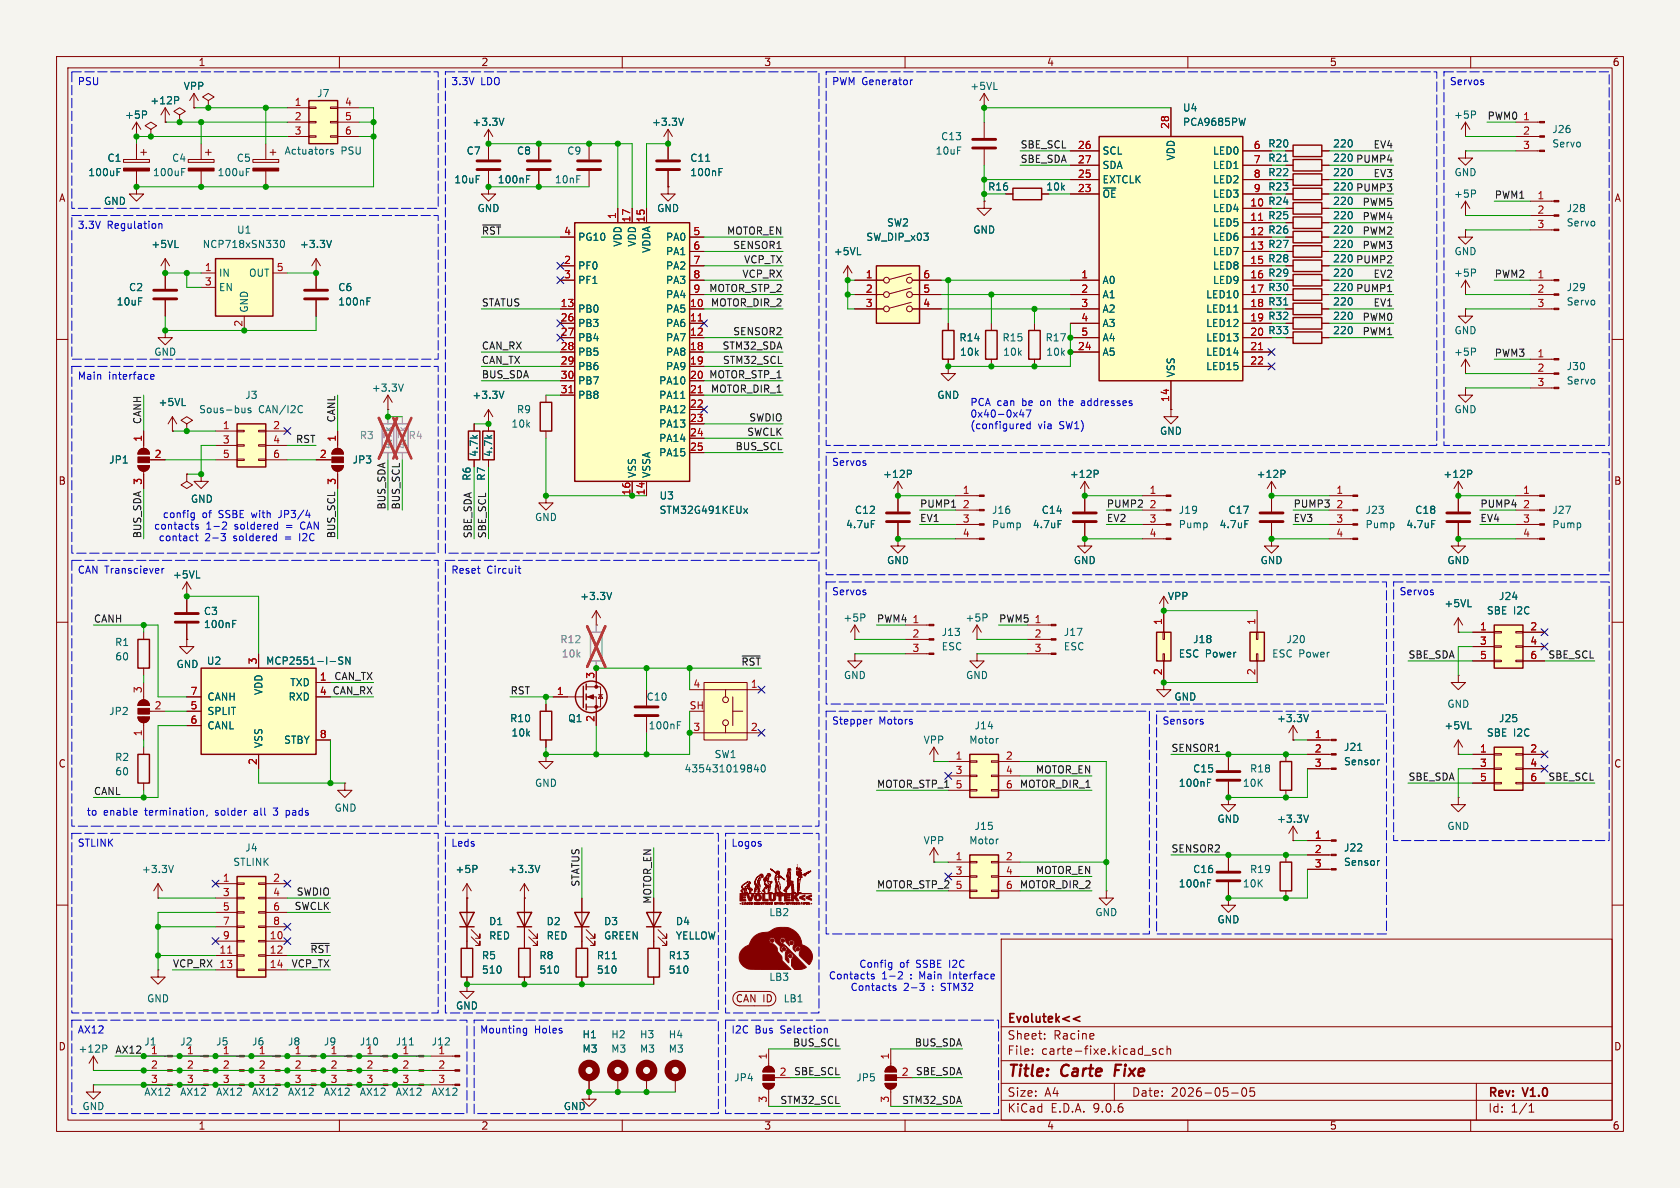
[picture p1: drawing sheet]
<svg xmlns="http://www.w3.org/2000/svg" width="297mm" height="210mm" viewBox="0 0 297 210" stroke-linecap="round" stroke-linejoin="round" font-family="sans-serif">
<defs><g id="words">
<g font-size="2.8" fill="#840000">
<text x="178" y="190.9">Title:</text>
<text x="187.7" y="190.9">Carte</text>
<text x="197.9" y="190.9">Fixe</text>
</g>
<g font-size="2.1" fill="#840000">
<text x="178" y="184">Sheet:</text>
<text x="178" y="181.2">Evolutek&lt;&lt;</text>
<text x="186.2" y="184">Racine</text>
<text x="178" y="186.7">File:</text>
<text x="184.1" y="186.7">carte-fixe.kicad_sch</text>
<text x="178" y="196.9">KiCad</text>
<text x="178" y="194.1">Size:</text>
<text x="184.7" y="194.1">A4</text>
<text x="185.7" y="196.9">E.D.A.</text>
<text x="193.3" y="196.9">9.0.6</text>
<text x="200" y="194.1">Date:</text>
<text x="207" y="194.1">2026-05-05</text>
<text x="263" y="194.3">Rev:</text>
<text x="263" y="196.9">Id:</text>
<text x="267.1" y="196.9">1/1</text>
<text x="269.4" y="194.3">V1.0</text>
</g>
<g font-size="1.8" fill="#840000">
<text x="35" y="11.9">1</text>
<text x="85" y="11.9">2</text>
<text x="135" y="11.9">3</text>
<text x="185" y="11.9">4</text>
<text x="235" y="11.9">5</text>
<text x="285" y="11.9">6</text>
<text x="10.3" y="35.9">A</text>
<text x="285.3" y="35.9">A</text>
<text x="10.3" y="85.9">B</text>
<text x="285.3" y="85.9">B</text>
<text x="10.3" y="135.9">C</text>
<text x="285.3" y="135.9">C</text>
<text x="130" y="177.4">CAN ID</text>
<text x="10.3" y="185.9">D</text>
<text x="285.3" y="185.9">D</text>
<text x="35" y="199.9">1</text>
<text x="85" y="199.9">2</text>
<text x="135" y="199.9">3</text>
<text x="185" y="199.9">4</text>
<text x="235" y="199.9">5</text>
<text x="285" y="199.9">6</text>
</g>
<g font-size="1.8" fill="#0000c2">
<text x="13.7" y="15.4">PSU</text>
<text x="79.7" y="15.4">3.3V</text>
<text x="85" y="15.4">LDO</text>
<text x="147" y="15.4">PWM Generator</text>
<text x="256.2" y="15.4">Servos</text>
<text x="13.7" y="40.8">3.3V</text>
<text x="18.9" y="40.8">Regulation</text>
<text x="13.7" y="67.4">Main</text>
<text x="19.2" y="67.4">interface</text>
<text x="171.4" y="71.9">PCA can</text>
<text x="180.8" y="71.9">be</text>
<text x="184.2" y="71.9">on</text>
<text x="187.7" y="71.9">the</text>
<text x="191.8" y="71.9">addresses</text>
<text x="171.4" y="73.9">0x40-0x47</text>
<text x="171.4" y="76">(configured</text>
<text x="183.5" y="76">via</text>
<text x="187.4" y="76">SW1)</text>
<text x="147" y="82.7">Servos</text>
<text x="27.1" y="93.8">contacts</text>
<text x="28" y="95.9">contact</text>
<text x="28.7" y="91.8">config</text>
<text x="35.7" y="91.8">of</text>
<text x="36.2" y="95.9">2-3</text>
<text x="36.4" y="93.8">1-2</text>
<text x="38.8" y="91.8">SSBE</text>
<text x="41.4" y="95.9">soldered</text>
<text x="41.6" y="93.8">soldered</text>
<text x="44.8" y="91.8">with</text>
<text x="49.8" y="91.8">JP3/4</text>
<text x="50.6" y="95.9">=</text>
<text x="50.9" y="93.8">=</text>
<text x="53.4" y="95.9">I2C</text>
<text x="53.6" y="93.8">CAN</text>
<text x="13.7" y="101.7">CAN Transciever</text>
<text x="79.7" y="101.7">Reset</text>
<text x="86.1" y="101.7">Circuit</text>
<text x="147" y="105.5">Servos</text>
<text x="247.3" y="105.5">Servos</text>
<text x="147" y="128.4">Stepper</text>
<text x="155.4" y="128.4">Motors</text>
<text x="205.4" y="128.4">Sensors</text>
<text x="13.7" y="150">STLINK</text>
<text x="15.2" y="144.3">to</text>
<text x="18.3" y="144.3">enable</text>
<text x="25.7" y="144.3">termination,</text>
<text x="38.3" y="144.3">solder</text>
<text x="45.4" y="144.3">all</text>
<text x="49" y="144.3">3</text>
<text x="51.4" y="144.3">pads</text>
<text x="79.7" y="150">Leds</text>
<text x="129.2" y="150">Logos</text>
<text x="146.4" y="173.3">Contacts</text>
<text x="151.8" y="171.3">Config</text>
<text x="155.9" y="173.3">1-2</text>
<text x="159" y="171.3">of</text>
<text x="161.1" y="173.3">:</text>
<text x="162.1" y="171.3">SSBE</text>
<text x="162.8" y="173.3">Main</text>
<text x="168.1" y="171.3">I2C</text>
<text x="168.4" y="173.3">Interface</text>
<text x="150.3" y="175.4">Contacts</text>
<text x="159.7" y="175.4">2-3</text>
<text x="164.9" y="175.4">:</text>
<text x="166.7" y="175.4">STM32</text>
<text x="13.7" y="183">AX12</text>
<text x="84.8" y="183">Mounting</text>
<text x="94.5" y="183">Holes</text>
<text x="129.2" y="183">I2C</text>
<text x="133.5" y="183">Bus</text>
<text x="138.1" y="183">Selection</text>
</g>
<g font-size="1.8" fill="#006464">
<text x="32.4" y="16.1">VPP</text>
<text x="56" y="17.4">J7</text>
<text x="171.4" y="16.1">+5VL</text>
<text x="22" y="21.2">+5P</text>
<text x="26.5" y="18.6">+12P</text>
<text x="83.4" y="22.5">+3.3V</text>
<text x="115.2" y="22.5">+3.3V</text>
<text x="209" y="19.9">U4</text>
<text x="209" y="22.5">PCA9685PW</text>
<text x="257" y="21.2">+5P</text>
<text x="274.3" y="23.7">J26</text>
<text x="18.9" y="28.8">C1</text>
<text x="30.3" y="28.8">C4</text>
<text x="41.8" y="28.8">C5</text>
<text x="50.2" y="27.5">Actuators</text>
<text x="60.3" y="27.5">PSU</text>
<text x="82.4" y="27.5">C7</text>
<text x="91.3" y="27.5">C8</text>
<text x="100.2" y="27.5">C9</text>
<text x="121.9" y="28.8">C11</text>
<text x="165.3" y="27.5">10uF</text>
<text x="166.3" y="25">C13</text>
<text x="194.8" y="27.5">SCL</text>
<text x="207.9" y="28.5" transform="rotate(-90 207.9 28.5)">VDD</text>
<text x="214.3" y="27.5">LED0</text>
<text x="224.1" y="26.3">R20</text>
<text x="224.1" y="28.8">R21</text>
<text x="235.6" y="26.3">220</text>
<text x="235.6" y="28.8">220</text>
<text x="274.3" y="26.3">Servo</text>
<text x="15.5" y="31.3">100uF</text>
<text x="26.9" y="31.3">100uF</text>
<text x="38.4" y="31.3">100uF</text>
<text x="80.2" y="32.6">10uF</text>
<text x="87.9" y="32.6">100nF</text>
<text x="98" y="32.6">10nF</text>
<text x="121.9" y="31.3">100nF</text>
<text x="174.6" y="33.9">R16</text>
<text x="184.9" y="33.9">10k</text>
<text x="194.8" y="30.1">SDA</text>
<text x="194.8" y="32.6">EXTCLK</text>
<text x="194.8" y="35.2">~{OE}</text>
<text x="214.3" y="30.1">LED1</text>
<text x="214.3" y="32.6">LED2</text>
<text x="214.3" y="35.2">LED3</text>
<text x="224.1" y="31.3">R22</text>
<text x="224.1" y="33.9">R23</text>
<text x="235.6" y="31.3">220</text>
<text x="235.6" y="33.9">220</text>
<text x="257" y="35.2">+5P</text>
<text x="257" y="31.3">GND</text>
<text x="18.3" y="36.4">GND</text>
<text x="41.8" y="41.5">U1</text>
<text x="84.3" y="37.7">GND</text>
<text x="116.1" y="37.7">GND</text>
<text x="156.7" y="40.2">SW2</text>
<text x="172" y="41.5">GND</text>
<text x="214.3" y="37.7">LED4</text>
<text x="214.3" y="40.2">LED5</text>
<text x="220.9" y="36.6">10 R24</text>
<text x="220.9" y="39.1">11 R25</text>
<text x="220.9" y="41.7">12 R26</text>
<text x="235.6" y="41.5">220</text>
<text x="235.6" y="39">220</text>
<text x="235.6" y="36.4">220</text>
<text x="276.9" y="40.2">Servo</text>
<text x="276.9" y="37.7">J28</text>
<text x="26.7" y="44">+5VL</text>
<text x="35.7" y="44">NCP718xSN330</text>
<text x="52.9" y="44">+3.3V</text>
<text x="102.1" y="42.8">PG10</text>
<text x="102.1" y="47.9">PF0</text>
<text x="110.1" y="43.7" transform="rotate(-90 110.1 43.7)">VDD</text>
<text x="112.6" y="43.7" transform="rotate(-90 112.6 43.7)">VDD</text>
<text x="115.2" y="44.8" transform="rotate(-90 115.2 44.8)">VDDA</text>
<text x="117.6" y="42.8">PA0</text>
<text x="117.6" y="45.3">PA1</text>
<text x="117.6" y="47.9">PA2</text>
<text x="147.3" y="45.3">+5VL</text>
<text x="153.1" y="42.8">SW_DIP_x03</text>
<text x="214.3" y="42.8">LED6</text>
<text x="214.3" y="45.3">LED7</text>
<text x="214.3" y="47.9">LED8</text>
<text x="220.9" y="44.2">13 R27</text>
<text x="220.9" y="46.7">15 R28</text>
<text x="235.6" y="44">220</text>
<text x="235.6" y="46.6">220</text>
<text x="257" y="45.3">GND</text>
<text x="22.7" y="51.7">C2</text>
<text x="38.6" y="49.1">IN</text>
<text x="38.6" y="51.7">EN</text>
<text x="43.9" y="49.1">OUT</text>
<text x="59.7" y="51.7">C6</text>
<text x="102.1" y="50.4">PF1</text>
<text x="117.6" y="50.4">PA3</text>
<text x="117.6" y="52.9">PA4</text>
<text x="194.8" y="50.4">A0</text>
<text x="194.8" y="52.9">A1</text>
<text x="213.1" y="52.9">LED10</text>
<text x="214.3" y="50.4">LED9</text>
<text x="220.9" y="49.3">16 R29</text>
<text x="220.9" y="51.8">17 R30</text>
<text x="235.6" y="49.1">220</text>
<text x="235.6" y="51.7">220</text>
<text x="257" y="49.1">+5P</text>
<text x="276.9" y="51.7">J29</text>
<text x="20.5" y="54.2">10uF</text>
<text x="44" y="55.4" transform="rotate(-90 44 55.4)">GND</text>
<text x="59.7" y="54.2">100nF</text>
<text x="102.1" y="55.5">PB0</text>
<text x="102.1" y="58">PB3</text>
<text x="117.6" y="55.5">PA5</text>
<text x="117.6" y="58">PA6</text>
<text x="194.8" y="55.5">A2</text>
<text x="194.8" y="58">A3</text>
<text x="213.1" y="55.5">LED11</text>
<text x="213.1" y="58">LED12</text>
<text x="220.9" y="54.4">18 R31</text>
<text x="220.9" y="56.9">19 R32</text>
<text x="220.9" y="59.4">20 R33</text>
<text x="235.6" y="54.2">220</text>
<text x="235.6" y="56.7">220</text>
<text x="235.6" y="59.3">220</text>
<text x="257" y="59.3">GND</text>
<text x="276.9" y="54.2">Servo</text>
<text x="27.2" y="63.1">GND</text>
<text x="102.1" y="60.6">PB4</text>
<text x="102.1" y="63.1">PB5</text>
<text x="102.1" y="65.6">PB6</text>
<text x="117.6" y="60.6">PA7</text>
<text x="117.6" y="63.1">PA8</text>
<text x="117.6" y="65.6">PA9</text>
<text x="169.5" y="60.6">R14</text>
<text x="169.6" y="63.1">10k</text>
<text x="177.1" y="60.6">R15</text>
<text x="177.2" y="63.1">10k</text>
<text x="184.7" y="60.6">R17</text>
<text x="184.9" y="63.1">10k</text>
<text x="194.8" y="60.6">A4</text>
<text x="194.8" y="63.1">A5</text>
<text x="213.1" y="60.6">LED13</text>
<text x="213.1" y="63.1">LED14</text>
<text x="213.1" y="65.6">LED15</text>
<text x="257" y="63.1">+5P</text>
<text x="276.9" y="65.6">J30</text>
<text x="27.9" y="72">+5VL</text>
<text x="43.3" y="70.7">J3</text>
<text x="65.6" y="69.4">+3.3V</text>
<text x="83.4" y="70.7">+3.3V</text>
<text x="102.1" y="68.2">PB7</text>
<text x="102.1" y="70.7">PB8</text>
<text x="116.4" y="68.2">PA10</text>
<text x="116.4" y="70.7">PA11</text>
<text x="165.6" y="70.7">GND</text>
<text x="207.9" y="66.8" transform="rotate(-90 207.9 66.8)">VSS</text>
<text x="276.9" y="68.2">Servo</text>
<text x="35.1" y="73.3">Sous-bus</text>
<text x="45.7" y="73.3">CAN/I2C</text>
<text x="90.3" y="75.8">10k</text>
<text x="91.3" y="73.3">R9</text>
<text x="116.4" y="73.3">PA12</text>
<text x="116.4" y="75.8">PA13</text>
<text x="205" y="77.1">GND</text>
<text x="257" y="73.3">GND</text>
<text x="19.2" y="82.1">JP1</text>
<text x="62.2" y="82.1">JP3</text>
<text x="84.7" y="80.9" transform="rotate(-90 84.7 80.9)">4.7k</text>
<text x="87.2" y="80.9" transform="rotate(-90 87.2 80.9)">4.7k</text>
<text x="116.4" y="78.3">PA14</text>
<text x="116.4" y="80.9">PA15</text>
<text x="33.7" y="89.1">GND</text>
<text x="83.4" y="85.1" transform="rotate(-90 83.4 85.1)">R6</text>
<text x="86" y="85.1" transform="rotate(-90 86 85.1)">R7</text>
<text x="112.6" y="84.6" transform="rotate(-90 112.6 84.6)">VSS</text>
<text x="115.2" y="84.6" transform="rotate(-90 115.2 84.6)">VSSA</text>
<text x="116.5" y="88.5">U3</text>
<text x="156" y="84.7">+12P</text>
<text x="189" y="84.7">+12P</text>
<text x="222.1" y="84.7">+12P</text>
<text x="255.1" y="84.7">+12P</text>
<text x="94.5" y="92.3">GND</text>
<text x="116.5" y="91">STM32G491KEUx</text>
<text x="149.5" y="93.6">4.7uF</text>
<text x="151" y="91">C12</text>
<text x="175.3" y="93.6">Pump</text>
<text x="175.3" y="91">J16</text>
<text x="182.5" y="93.6">4.7uF</text>
<text x="184.1" y="91">C14</text>
<text x="208.3" y="93.6">Pump</text>
<text x="208.3" y="91">J19</text>
<text x="215.5" y="93.6">4.7uF</text>
<text x="217.1" y="91">C17</text>
<text x="241.3" y="93.6">Pump</text>
<text x="241.3" y="91">J23</text>
<text x="248.5" y="93.6">4.7uF</text>
<text x="250.1" y="91">C18</text>
<text x="274.3" y="93.6">Pump</text>
<text x="274.3" y="91">J27</text>
<text x="156.7" y="99.9">GND</text>
<text x="189.7" y="99.9">GND</text>
<text x="222.8" y="99.9">GND</text>
<text x="255.8" y="99.9">GND</text>
<text x="30.5" y="102.5">+5VL</text>
<text x="102.5" y="106.3">+3.3V</text>
<text x="206.4" y="106.3">VPP</text>
<text x="255.3" y="107.5">+5VL</text>
<text x="264.9" y="106.3">J24</text>
<text x="36" y="108.9">C3</text>
<text x="36" y="111.2">100nF</text>
<text x="149" y="110.1">+5P</text>
<text x="166.4" y="112.6">J13</text>
<text x="170.6" y="110.1">+5P</text>
<text x="188" y="112.6">J17</text>
<text x="210.8" y="113.9">J18</text>
<text x="227.3" y="113.9">J20</text>
<text x="262.8" y="108.8">SBE</text>
<text x="267.6" y="108.8">I2C</text>
<text x="20.2" y="114.4">R1</text>
<text x="20.3" y="116.9">60</text>
<text x="31.1" y="118.3">GND</text>
<text x="36.5" y="117.7">U2</text>
<text x="46.9" y="117.7">MCP2551-I-SN</text>
<text x="166.4" y="115.2">ESC</text>
<text x="188" y="115.2">ESC</text>
<text x="208.3" y="116.4">ESC Power</text>
<text x="224.8" y="116.4">ESC Power</text>
<text x="36.6" y="124.1">CANH</text>
<text x="46.6" y="123" transform="rotate(-90 46.6 123)">VDD</text>
<text x="50.9" y="124.1">RXD</text>
<text x="51.2" y="121.5">TXD</text>
<text x="114.2" y="124.1">C10</text>
<text x="149.1" y="120.2">GND</text>
<text x="170.7" y="120.2">GND</text>
<text x="207.5" y="124.1">GND</text>
<text x="255.8" y="125.3">GND</text>
<text x="19.2" y="126.6">JP2</text>
<text x="36.6" y="126.6">SPLIT</text>
<text x="36.6" y="129.1">CANL</text>
<text x="50.1" y="131.7">STBY</text>
<text x="90.1" y="127.9">R10</text>
<text x="90.3" y="130.4">10k</text>
<text x="100.3" y="127.9">Q1</text>
<text x="114.6" y="129.1">100nF</text>
<text x="163.2" y="131.7">VPP</text>
<text x="171.3" y="131.7">Motor</text>
<text x="172.2" y="129.1">J14</text>
<text x="225.7" y="127.9">+3.3V</text>
<text x="255.3" y="129.1">+5VL</text>
<text x="262.8" y="130.4">SBE</text>
<text x="264.9" y="127.9">J25</text>
<text x="267.6" y="130.4">I2C</text>
<text x="20.2" y="134.7">R2</text>
<text x="20.3" y="137.3">60</text>
<text x="46.6" y="132.3" transform="rotate(-90 46.6 132.3)">VSS</text>
<text x="120.9" y="136.8">435431019840</text>
<text x="126.2" y="134.2">SW1</text>
<text x="210.8" y="136.8">C15</text>
<text x="220.9" y="136.8">R18</text>
<text x="237.5" y="132.9">J21</text>
<text x="237.5" y="135.5">Sensor</text>
<text x="59.1" y="143.7">GND</text>
<text x="94.5" y="139.3">GND</text>
<text x="208.3" y="139.3">100nF</text>
<text x="219.6" y="139.3">10K</text>
<text x="163.2" y="149.5">VPP</text>
<text x="171.3" y="149.5">Motor</text>
<text x="172.2" y="146.9">J15</text>
<text x="215.1" y="145.6">GND</text>
<text x="225.7" y="145.6">+3.3V</text>
<text x="255.8" y="146.9">GND</text>
<text x="25" y="154.5">+3.3V</text>
<text x="41.1" y="153.3">STLINK</text>
<text x="43.3" y="150.7">J4</text>
<text x="80.4" y="154.5">+5P</text>
<text x="89.8" y="154.5">+3.3V</text>
<text x="210.8" y="154.5">C16</text>
<text x="220.9" y="154.5">R19</text>
<text x="237.5" y="150.7">J22</text>
<text x="237.5" y="153.3">Sensor</text>
<text x="208.3" y="157.1">100nF</text>
<text x="219.6" y="157.1">10K</text>
<text x="86.4" y="163.7">D1</text>
<text x="86.4" y="166.3">RED</text>
<text x="96.5" y="163.7">D2</text>
<text x="96.5" y="166.3">RED</text>
<text x="106.7" y="163.7">D3</text>
<text x="106.7" y="166.3">GREEN</text>
<text x="119.4" y="163.7">D4</text>
<text x="119.4" y="166.3">YELLOW</text>
<text x="135.9" y="162.2">LB2</text>
<text x="193.5" y="162.2">GND</text>
<text x="215.1" y="163.4">GND</text>
<text x="85.1" y="169.8">R5</text>
<text x="85.1" y="172.3">510</text>
<text x="95.3" y="169.8">R8</text>
<text x="95.3" y="172.3">510</text>
<text x="105.4" y="172.3">510</text>
<text x="105.4" y="169.8">R11</text>
<text x="118.1" y="172.3">510</text>
<text x="118.1" y="169.8">R13</text>
<text x="135.9" y="173.6">LB3</text>
<text x="25.9" y="177.4">GND</text>
<text x="80.5" y="178.7">GND</text>
<text x="138.4" y="177.4">LB1</text>
<text x="31.8" y="185">J2</text>
<text x="38.1" y="185">J5</text>
<text x="44.5" y="185">J6</text>
<text x="50.8" y="185">J8</text>
<text x="57.2" y="185">J9</text>
<text x="63.5" y="185">J10</text>
<text x="69.9" y="185">J11</text>
<text x="76.2" y="185">J12</text>
<text x="102.9" y="183.7">H1</text>
<text x="108" y="183.7">H2</text>
<text x="113" y="183.7">H3</text>
<text x="118.1" y="183.7">H4</text>
<text x="13.8" y="186.3">+12P</text>
<text x="26.6" y="186.4">1</text>
<text x="32.9" y="186.4">1</text>
<text x="39.3" y="186.4">1</text>
<text x="45.6" y="186.4">1</text>
<text x="52" y="186.4">1</text>
<text x="58.3" y="186.4">1</text>
<text x="64.7" y="186.4">1</text>
<text x="71" y="186.4">1</text>
<text x="77.4" y="186.4">1</text>
<text x="102.9" y="186.3">M3</text>
<text x="108" y="186.3">M3</text>
<text x="113" y="186.3">M3</text>
<text x="118.1" y="186.3">M3</text>
<text x="129.7" y="191.4">JP4</text>
<text x="151.3" y="191.4">JP5</text>
<text x="14.5" y="196.4">GND</text>
<text x="25.4" y="193.9">AX12</text>
<text x="31.8" y="193.9">AX12</text>
<text x="38.1" y="193.9">AX12</text>
<text x="44.5" y="193.9">AX12</text>
<text x="50.8" y="193.9">AX12</text>
<text x="57.2" y="193.9">AX12</text>
<text x="63.5" y="193.9">AX12</text>
<text x="69.9" y="193.9">AX12</text>
<text x="76.2" y="193.9">AX12</text>
<text x="99.6" y="196.4">GND</text>
</g>
<g font-size="1.8" fill="#a90000">
<text x="52" y="18.8">1</text>
<text x="52" y="21.3">2</text>
<text x="52" y="23.9">3</text>
<text x="60.9" y="18.8">4</text>
<text x="60.9" y="21.3">5</text>
<text x="60.9" y="23.9">6</text>
<text x="206.8" y="22.9" transform="rotate(-90 206.8 22.9)">28</text>
<text x="269.2" y="21.3">1</text>
<text x="269.2" y="23.9">2</text>
<text x="190.5" y="26.4">26</text>
<text x="190.5" y="29">27</text>
<text x="221.5" y="26.4">6</text>
<text x="221.5" y="29">7</text>
<text x="269.2" y="26.4">3</text>
<text x="190.5" y="31.5">25</text>
<text x="190.5" y="34">23</text>
<text x="221.5" y="31.5">8</text>
<text x="221.5" y="34">9</text>
<text x="271.7" y="35.3">1</text>
<text x="99.6" y="41.7">4</text>
<text x="109" y="38.8" transform="rotate(-90 109 38.8)">1</text>
<text x="111.5" y="39.4" transform="rotate(-90 111.5 39.4)">17</text>
<text x="114" y="39.4" transform="rotate(-90 114 39.4)">15</text>
<text x="122.5" y="41.7">5</text>
<text x="271.7" y="37.8">2</text>
<text x="271.7" y="40.4">3</text>
<text x="99.6" y="46.7">2</text>
<text x="122.5" y="44.2">6</text>
<text x="122.5" y="46.7">7</text>
<text x="36.1" y="48">1</text>
<text x="36.1" y="50.5">3</text>
<text x="48.8" y="48">5</text>
<text x="99.6" y="49.3">3</text>
<text x="122.5" y="49.3">8</text>
<text x="122.5" y="51.8">9</text>
<text x="153" y="49.3">1</text>
<text x="153" y="51.8">2</text>
<text x="163.1" y="49.3">6</text>
<text x="163.1" y="51.8">5</text>
<text x="191.1" y="49.3">1</text>
<text x="191.1" y="51.8">2</text>
<text x="271.7" y="49.3">1</text>
<text x="271.7" y="51.8">2</text>
<text x="42.9" y="57.9" transform="rotate(-90 42.9 57.9)">2</text>
<text x="99" y="54.4">13</text>
<text x="99" y="56.9">26</text>
<text x="99" y="59.4">27</text>
<text x="121.9" y="54.4">10</text>
<text x="121.9" y="56.9">11</text>
<text x="121.9" y="59.4">12</text>
<text x="153" y="54.4">3</text>
<text x="163.1" y="54.4">4</text>
<text x="191.1" y="54.4">3</text>
<text x="191.1" y="56.9">4</text>
<text x="191.1" y="59.4">5</text>
<text x="271.7" y="54.4">3</text>
<text x="99" y="62">28</text>
<text x="99" y="64.5">29</text>
<text x="121.9" y="62">18</text>
<text x="121.9" y="64.5">19</text>
<text x="190.5" y="62">24</text>
<text x="220.9" y="62">21</text>
<text x="220.9" y="64.5">22</text>
<text x="271.7" y="63.2">1</text>
<text x="271.7" y="65.8">2</text>
<text x="99" y="67.1">30</text>
<text x="99" y="69.6">31</text>
<text x="121.9" y="67.1">20</text>
<text x="121.9" y="69.6">21</text>
<text x="206.8" y="71.2" transform="rotate(-90 206.8 71.2)">14</text>
<text x="271.7" y="68.3">3</text>
<text x="39.3" y="75.9">1</text>
<text x="48.2" y="75.9">2</text>
<text x="121.9" y="72.1">22</text>
<text x="121.9" y="74.7">23</text>
<text x="121.9" y="77.2">24</text>
<text x="25.1" y="78.2" transform="rotate(-90 25.1 78.2)">1</text>
<text x="27.2" y="81">2</text>
<text x="39.3" y="78.5">3</text>
<text x="39.3" y="81">5</text>
<text x="48.2" y="78.5">4</text>
<text x="48.2" y="81">6</text>
<text x="56.4" y="81">2</text>
<text x="59.4" y="78.2" transform="rotate(-90 59.4 78.2)">1</text>
<text x="121.9" y="79.8">25</text>
<text x="25.1" y="85.8" transform="rotate(-90 25.1 85.8)">3</text>
<text x="59.4" y="85.8" transform="rotate(-90 59.4 85.8)">3</text>
<text x="111.5" y="87.7" transform="rotate(-90 111.5 87.7)">16</text>
<text x="114" y="87.7" transform="rotate(-90 114 87.7)">14</text>
<text x="170.1" y="87.4">1</text>
<text x="170.1" y="89.9">2</text>
<text x="203.1" y="87.4">1</text>
<text x="203.1" y="89.9">2</text>
<text x="236.1" y="87.4">1</text>
<text x="236.1" y="89.9">2</text>
<text x="269.2" y="87.4">1</text>
<text x="269.2" y="89.9">2</text>
<text x="170.1" y="92.5">3</text>
<text x="170.1" y="95">4</text>
<text x="203.1" y="92.5">3</text>
<text x="203.1" y="95">4</text>
<text x="236.1" y="92.5">3</text>
<text x="236.1" y="95">4</text>
<text x="269.2" y="92.5">3</text>
<text x="269.2" y="95">4</text>
<text x="161.2" y="110.2">1</text>
<text x="161.2" y="112.8">2</text>
<text x="182.8" y="110.2">1</text>
<text x="182.8" y="112.8">2</text>
<text x="205.5" y="110.6" transform="rotate(-90 205.5 110.6)">1</text>
<text x="222" y="110.6" transform="rotate(-90 222 110.6)">1</text>
<text x="261.5" y="111.5">1</text>
<text x="270.4" y="111.5">2</text>
<text x="45.5" y="117.5" transform="rotate(-90 45.5 117.5)">3</text>
<text x="161.2" y="115.3">3</text>
<text x="182.8" y="115.3">3</text>
<text x="205.5" y="119.5" transform="rotate(-90 205.5 119.5)">2</text>
<text x="222" y="119.5" transform="rotate(-90 222 119.5)">2</text>
<text x="261.5" y="114">3</text>
<text x="261.5" y="116.6">5</text>
<text x="270.4" y="114">4</text>
<text x="270.4" y="116.6">6</text>
<text x="25.1" y="122.6" transform="rotate(-90 25.1 122.6)">3</text>
<text x="27.2" y="125.5">2</text>
<text x="33.6" y="122.9">7</text>
<text x="33.6" y="125.5">5</text>
<text x="56.4" y="120.4">1</text>
<text x="56.4" y="122.9">4</text>
<text x="98.4" y="122.9">1</text>
<text x="105.2" y="120.1" transform="rotate(-90 105.2 120.1)">3</text>
<text x="121.8" y="125.5">SH</text>
<text x="122.5" y="121.7">4</text>
<text x="132.6" y="121.7">1</text>
<text x="25.1" y="130.2" transform="rotate(-90 25.1 130.2)">1</text>
<text x="33.6" y="128">6</text>
<text x="56.4" y="130.6">8</text>
<text x="105.2" y="127.7" transform="rotate(-90 105.2 127.7)">2</text>
<text x="122.5" y="129.3">3</text>
<text x="132.6" y="129.3">2</text>
<text x="232.3" y="130.6">1</text>
<text x="45.5" y="135.3" transform="rotate(-90 45.5 135.3)">2</text>
<text x="168.8" y="134.4">1</text>
<text x="168.8" y="136.9">3</text>
<text x="177.7" y="134.4">2</text>
<text x="177.7" y="136.9">4</text>
<text x="232.3" y="133.1">2</text>
<text x="232.3" y="135.6">3</text>
<text x="261.5" y="133.1">1</text>
<text x="261.5" y="135.6">3</text>
<text x="270.4" y="133.1">2</text>
<text x="270.4" y="135.6">4</text>
<text x="168.8" y="139.4">5</text>
<text x="177.7" y="139.4">6</text>
<text x="261.5" y="138.2">5</text>
<text x="270.4" y="138.2">6</text>
<text x="232.3" y="148.3">1</text>
<text x="39.3" y="156">1</text>
<text x="48.2" y="156">2</text>
<text x="168.8" y="152.1">1</text>
<text x="168.8" y="154.7">3</text>
<text x="177.7" y="152.1">2</text>
<text x="177.7" y="154.7">4</text>
<text x="232.3" y="150.9">2</text>
<text x="232.3" y="153.4">3</text>
<text x="39.3" y="158.5">3</text>
<text x="39.3" y="161">5</text>
<text x="48.2" y="158.5">4</text>
<text x="48.2" y="161">6</text>
<text x="168.8" y="157.2">5</text>
<text x="177.7" y="157.2">6</text>
<text x="39.3" y="163.6">7</text>
<text x="39.3" y="166.1">9</text>
<text x="47.6" y="166.1">10</text>
<text x="48.2" y="163.6">8</text>
<text x="38.7" y="168.7">11</text>
<text x="47.6" y="168.7">12</text>
<text x="47.6" y="171.2">14</text>
<text x="26.6" y="189">2</text>
<text x="26.6" y="191.5">3</text>
<text x="32.9" y="189">2</text>
<text x="32.9" y="191.5">3</text>
<text x="39.3" y="189">2</text>
<text x="39.3" y="191.5">3</text>
<text x="45.6" y="189">2</text>
<text x="45.6" y="191.5">3</text>
<text x="52" y="189">2</text>
<text x="52" y="191.5">3</text>
<text x="58.3" y="189">2</text>
<text x="58.3" y="191.5">3</text>
<text x="64.7" y="189">2</text>
<text x="64.7" y="191.5">3</text>
<text x="71" y="189">2</text>
<text x="71" y="191.5">3</text>
<text x="77.4" y="189">2</text>
<text x="77.4" y="191.5">3</text>
<text x="135.6" y="187.4" transform="rotate(-90 135.6 187.4)">1</text>
<text x="137.7" y="190.2">2</text>
<text x="157.2" y="187.4" transform="rotate(-90 157.2 187.4)">1</text>
<text x="159.3" y="190.2">2</text>
<text x="135.6" y="195" transform="rotate(-90 135.6 195)">3</text>
<text x="157.2" y="195" transform="rotate(-90 157.2 195)">3</text>
</g>
<g font-size="1.8" fill="#0f0f0f">
<text x="262.9" y="21.2">PWM0</text>
<text x="180.3" y="26.3">SBE_SCL</text>
<text x="180.3" y="28.9">SBE_SDA</text>
<text x="235.6" y="28.8">220 PUMP4</text>
<text x="242.7" y="26.3">EV4</text>
<text x="235.6" y="33.9">220 PUMP3</text>
<text x="242.7" y="31.4">EV3</text>
<text x="264.2" y="35.2">PWM1</text>
<text x="85.1" y="41.6">~{RST}</text>
<text x="128.4" y="41.6">MOTOR_EN</text>
<text x="240.8" y="41.6">PWM2</text>
<text x="240.8" y="39">PWM4</text>
<text x="240.8" y="36.5">PWM5</text>
<text x="129.5" y="44.1">SENSOR1</text>
<text x="131.5" y="46.6">VCP_TX</text>
<text x="235.6" y="46.6">220 PUMP2</text>
<text x="240.8" y="44.1">PWM3</text>
<text x="125.3" y="51.7">MOTOR_STP_2</text>
<text x="131.2" y="49.2">VCP_RX</text>
<text x="235.6" y="51.7">220 PUMP1</text>
<text x="242.7" y="49.2">EV2</text>
<text x="264.2" y="49.2">PWM2</text>
<text x="85.1" y="54.3">STATUS</text>
<text x="125.6" y="54.3">MOTOR_DIR_2</text>
<text x="129.5" y="59.3">SENSOR2</text>
<text x="240.8" y="59.3">PWM1</text>
<text x="240.8" y="56.8">PWM0</text>
<text x="242.7" y="54.3">EV1</text>
<text x="85.1" y="64.4">CAN_TX</text>
<text x="85.1" y="61.9">CAN_RX</text>
<text x="127.6" y="61.9">STM32_SDA</text>
<text x="127.7" y="64.4">STM32_SCL</text>
<text x="264.2" y="63.2">PWM3</text>
<text x="85.1" y="67">BUS_SDA</text>
<text x="125.3" y="67">MOTOR_STP_1</text>
<text x="125.6" y="69.5">MOTOR_DIR_1</text>
<text x="25.1" y="75.1" transform="rotate(-90 25.1 75.1)">CANH</text>
<text x="59.3" y="74.8" transform="rotate(-90 59.3 74.8)">CANL</text>
<text x="132" y="77.1">SWCLK</text>
<text x="132.4" y="74.6">SWDIO</text>
<text x="52.2" y="78.4">RST</text>
<text x="129.9" y="79.7">BUS_SCL</text>
<text x="162.6" y="89.8">PUMP1</text>
<text x="195.6" y="89.8">PUMP2</text>
<text x="228.6" y="89.8">PUMP3</text>
<text x="261.6" y="89.8">PUMP4</text>
<text x="25.1" y="95.3" transform="rotate(-90 25.1 95.3)">BUS_SDA 3</text>
<text x="59.3" y="95.3" transform="rotate(-90 59.3 95.3)">BUS_SCL</text>
<text x="68.2" y="90.2" transform="rotate(-90 68.2 90.2)">BUS_SDA</text>
<text x="70.8" y="90.2" transform="rotate(-90 70.8 90.2)">BUS_SCL</text>
<text x="83.5" y="95.3" transform="rotate(-90 83.5 95.3)">SBE_SDA</text>
<text x="86" y="95.3" transform="rotate(-90 86 95.3)">SBE_SCL</text>
<text x="162.6" y="92.4">EV1</text>
<text x="195.6" y="92.4">EV2</text>
<text x="228.6" y="92.4">EV3</text>
<text x="261.6" y="92.4">EV4</text>
<text x="16.5" y="110.1">CANH</text>
<text x="154.9" y="110.1">PWM4</text>
<text x="176.5" y="110.1">PWM5</text>
<text x="131" y="117.8">~{RST}</text>
<text x="248.9" y="116.5">SBE_SDA</text>
<text x="273.6" y="116.5">SBE_SCL</text>
<text x="58.7" y="122.8">CAN_RX</text>
<text x="59" y="120.3">CAN_TX</text>
<text x="90.2" y="122.8">RST</text>
<text x="183" y="136.8">MOTOR_EN</text>
<text x="207" y="133">SENSOR1</text>
<text x="16.5" y="140.6">CANL</text>
<text x="154.9" y="139.4">MOTOR_STP_1</text>
<text x="180.2" y="139.4">MOTOR_DIR_1</text>
<text x="248.9" y="138.1">SBE_SDA</text>
<text x="273.6" y="138.1">SBE_SCL</text>
<text x="183" y="154.6">MOTOR_EN</text>
<text x="207" y="150.8">SENSOR2</text>
<text x="52" y="160.9">SWCLK</text>
<text x="52.4" y="158.4">SWDIO</text>
<text x="102.5" y="156.8" transform="rotate(-90 102.5 156.8)">STATUS</text>
<text x="115.2" y="159.9" transform="rotate(-90 115.2 159.9)">MOTOR_EN</text>
<text x="154.9" y="157.1">MOTOR_STP_2</text>
<text x="180.2" y="157.1">MOTOR_DIR_2</text>
<text x="30.5" y="171.1">VCP_RX 13</text>
<text x="51.4" y="171.1">VCP_TX</text>
<text x="54.8" y="168.6">~{RST}</text>
<text x="25.4" y="185">J1</text>
<text x="140.1" y="185.1">BUS_SCL</text>
<text x="161.6" y="185.1">BUS_SDA</text>
<text x="20.3" y="186.3">AX12</text>
<text x="140.3" y="190.2">SBE_SCL</text>
<text x="161.8" y="190.2">SBE_SDA</text>
<text x="137.9" y="195.2">STM32_SCL</text>
<text x="159.4" y="195.2">STM32_SDA</text>
</g>
<g font-size="1.8" fill="#939391">
<text x="63.5" y="77.8">R3</text>
<text x="72.1" y="77.8">R4</text>
<text x="69.4" y="79.5" transform="rotate(-90 69.4 79.5)">4.7k</text>
<text x="72" y="79.5" transform="rotate(-90 72 79.5)">4.7k</text>
<text x="99" y="113.9">R12</text>
<text x="99.2" y="116.4">10k</text>
</g>
</g></defs>
<path d="M0 0h297v210h-297z" fill="#f5f4ef" stroke="#f5f4ef" stroke-width=".18"/>
<g fill="none" stroke="#840000" stroke-width=".18">
<path d="M10 10h277v190h-277zM12 12h273v186h-273zM60 10v2M110 10v2M160 10v2M210 10v2M260 10v2M177.8 34.3h1.3M184.1 34.3h1.3M10 60h2M285 60h2M10 110h2"/>
<path d="M285 110h2M10 160h2M177 166h108v32h-108zM285 160h2M60 198v2M110 198v2M160 198v2M177 194.5h108M177 191.5h108M177 187.5h108M177 181.5h108M182.5 186.3v.1"/>
<path d="M182.5 185.5v.1M184.7 183.6v.1M184.7 182.8v.1M193.3 182.8l.1 .3-.7 .1M197 191.5v3M202.3 186.5h1.2M204.3 185.5l-.3-.1-.3 .2 .1 .2 .5 .2v.3h-.6M205.7 185.5l-.5-.1-.2 .3v.4l.1 .2h.6M206.3 185.5l.2-.1 .4 .1 .1 .9M206.3 184.9v1.5M210 198v2M217.7 193.2h1.2"/>
<path d="M219.7 192.4l.2-.1a.81 .81 0 0 1 .6 .6 .81 .81 0 0 1-.3 .8l-.2 .1a.81 .81 0 0 1-.3-1.4zM221.7 192.3h-.7v.7l.2-.1h.5l.1 .3-.1 .5-.2 .1-.5-.1M260 198v2M261 191.5v6.5M270.3 196.6h.9M270.3 195.5l.4-.4v1.5"/>
</g>
<path d="M197.3 188.2l-.3 2" fill="none" stroke="#840000" stroke-width=".4"/>
<path d="M190.9 179.7l-1.1 .4 1.1 .4" fill="none" stroke="#840000" stroke-width=".3"/>
<path d="M179.1 33.3h5v2h-5z" fill="none" stroke="#840000" stroke-width=".25"/>
<path d="M154.9 47h7.7v10.2h-7.7z" fill="#ffffc2"/>
<g fill="none" stroke="#840000" stroke-width=".18">
<path d="M86.4 25.4h.1M86.4 33v1.3h1.2l-1.2 1.3-1.3-1.3h1.3M86.4 33h.1M86.4 22.9l-.8 1.2M86.4 22.9l.7 1.2M86.4 22.9v5.3M86.4 30.2v2.8M151.1 49.5h5.1M151.1 52.1h5.1M151.1 54.6h5.1M161.1 48.4l-3.9 1M161.1 50.9l-3.9 1"/>
<path d="M161.1 53.4l-3.9 1.1M161.3 49.5h5.1M161.3 52.1h5.1M161.3 54.6h5.1M68.6 72.4h.1M68.6 69.9l-.8 1.2M68.6 69.9l.7 1.2M68.6 69.9v2.5"/>
<circle cx="156.7" cy="49.5" r=".51"/>
<circle cx="156.7" cy="52.1" r=".51"/>
<circle cx="156.7" cy="54.6" r=".51"/>
<circle cx="160.8" cy="49.5" r=".51"/>
<circle cx="160.8" cy="52.1" r=".51"/>
<circle cx="160.8" cy="54.6" r=".51"/>
</g>
<path d="M154.9 47h7.7v10.2h-7.7z" fill="none" stroke="#840000" stroke-width=".25"/>
<path d="M89.1 20.9l-.4 1.3M71.3 67.9l-.4 1.3" fill="none" stroke="#006464" stroke-width=".18"/>
<path d="M84.3 28.4h4.1M84.3 30h4.1" fill="none" stroke="#840000" stroke-width=".51"/>
<path d="M124.5 120.7h7.6v10.1h-7.6z" fill="#ffffc2"/>
<g fill="none" stroke="#840000" stroke-width=".18">
<path d="M24.7 79.6a1.02 1.02 0 0 1 1.1-.3 1.02 1.02 0 0 1 .6 1h-2zM25.4 76.2v3M24.4 82.3h2a1.02 1.02 0 0 1-1 1 1.02 1.02 0 0 1-1-1zM25.4 83.3v3.1M26.4 81.3h2.8M105.4 110.5h.1M105.4 108l-.8 1.2M105.4 108l.8 1.2M105.4 108v2.5M96.5 133.4v1.2h1.3l-1.3 1.3-1.3-1.3h1.3M96.5 133.4h.1M121.9 121.9h12.7"/>
<path d="M121.9 129.5h12.7M124.5 120.7h7.6v10.1h-7.6zM128.3 121.9v1.3M128.3 128.3v1.2M129.5 125.7h1.8M129.5 123.2v5.1"/>
<circle cx="128.3" cy="123.7" r=".51"/>
<circle cx="128.3" cy="127.8" r=".51"/>
</g>
<path d="M108.1 104.7l-.4 1.3M133.7 135.1l-.4 .9h.8M134 135.6v.9M134.7 135.3l.2-.1a.68 .68 0 0 1 .4 .6 .68 .68 0 0 1-.4 .7l-.2-.2-.1-.3z" fill="none" stroke="#006464" stroke-width=".18"/>
<path d="M104.4 111.8h2v5h-2z" fill="none" stroke="#9c9b98" stroke-width=".25"/>
<path d="M105.4 110.5v1.3M105.4 116.8v1.3" fill="none" stroke="#9c9b98" stroke-width=".18"/>
<path d="M103.8 110.7l3.2 7.2M107 110.7l-3.2 7.2" fill="none" stroke="#e12e31" stroke-width=".46"/>
<g fill="#840000" stroke="#840000" stroke-width=".18">
<path d="M24.7 79.6a1.02 1.02 0 0 1 1.1-.3 1.02 1.02 0 0 1 .6 1h-2z"/>
<path d="M24.4 80.8h2v1h-2z"/>
<path d="M24.4 82.3h2a1.02 1.02 0 0 1-1 1 1.02 1.02 0 0 1-1-1z"/>
</g>
<path d="M194.3 24.1h25.4v43.2h-25.4z" fill="#ffffc2"/>
<path d="M194.3 24.1h25.4v43.2h-25.4zM228.6 25.7h5.1v2h-5.1zM95.5 71.1h2v5.1h-2z" fill="none" stroke="#840000" stroke-width=".25"/>
<g fill="none" stroke="#840000" stroke-width=".18">
<path d="M174 19.1h.1M174 16.5l-.8 1.3M174 16.5l.8 1.3M174 16.5v2.6M207 19.1v5M118.1 25.4h.1M118.1 22.9l-.8 1.2M118.1 22.9l.8 1.2M118.1 22.9v2.5M174 21.6v2.8M174 26.4v2.8M189.2 26.7h5.1"/>
<path d="M189.2 29.2h5.1M189.2 31.8h5.1M189.2 34.3h5.1M219.7 26.7h5.1M219.7 29.2h5.1M219.7 31.8h5.1M219.7 34.3h5.1M219.7 36.8h5.1M219.7 39.4h5.1M227.3 26.7h1.3M233.7 26.7h1.2M189.2 49.5h5.1"/>
<path d="M189.2 52.1h5.1M189.2 54.6h5.1M189.2 57.2h5.1M189.2 59.7h5.1M219.7 49.5h5.1M219.7 52.1h5.1M219.7 54.6h5.1M219.7 57.2h5.1M219.7 59.7h5.1M219.7 41.9h5.1M219.7 44.5h5.1M219.7 47h5.1"/>
<path d="M59 79.6a1.02 1.02 0 0 1 1.1-.3 1.02 1.02 0 0 1 .6 1h-2zM59.7 76.2v3M96.5 69.9v1.2M96.5 76.2v1.3M189.2 62.2h5.1M207 72.4v1.3h1.3l-1.3 1.2-1.3-1.2h1.3M207 72.4h.1M207 67.3v5.1M219.7 62.2h5.1M219.7 64.8h5.1M55.9 81.3h2.8M58.7 82.3h2a1.02 1.02 0 0 1-1 1 1.02 1.02 0 0 1-1-1z"/>
<path d="M59.7 83.3v3.1M257.8 111.8h.1M257.8 109.2l-.8 1.3M257.8 109.2l.8 1.3M257.8 109.2v2.6M257.8 133.4h.1M257.8 130.8v2.6M257.8 130.8l-.8 1.3M257.8 130.8l.8 1.3M130.8 177.8a1.27 1.27 0 0 1-1.2-1.3 1.27 1.27 0 0 1 1.2-1.2h5.1a1.27 1.27 0 0 1 1.3 1.2 1.27 1.27 0 0 1-1.3 1.3M50.8 186.7h4.2M50.8 189.2h4.2"/>
<path d="M50.8 191.8h4.2M57.1 186.7h4.3M57.1 189.2h4.3M57.1 191.8h4.3M63.5 186.7h4.2M63.5 189.2h4.2M63.5 191.8h4.2M69.8 186.7h4.3M69.8 189.2h4.3M69.8 191.8h4.3"/>
</g>
<path d="M175.7 15.8h.6M120.8 20.9l-.4 1.3M220.1 20.9l-.3 1.3M218.1 55.2h.8M259.5 107.3h.6M259.5 128.8h.6M72.4 184.7h.7" fill="none" stroke="#006464" stroke-width=".18"/>
<path d="M222.5 61.8h.7" fill="none" stroke="#a90000" stroke-width=".18"/>
<g fill="#840000" stroke="#840000" stroke-width=".18">
<path d="M55 186.6h.9v.2h-.9z"/>
<path d="M55 189.1h.9v.3h-.9z"/>
<path d="M55 191.6h.9v.3h-.9z"/>
<path d="M61.4 186.6h.8v.2h-.8z"/>
<path d="M61.4 189.1h.8v.3h-.8z"/>
<path d="M61.4 191.6h.8v.3h-.8z"/>
<path d="M67.7 186.6h.9v.2h-.9z"/>
<path d="M67.7 189.1h.9v.3h-.9z"/>
<path d="M67.7 191.6h.9v.3h-.9z"/>
<path d="M133.2 165.7a4.1 4.1 0 0 1 2.7-1 3.9 3.9 0 0 1 4.8 .1 4.6 4.6 0 0 1 1.2 2.3 2.04 2.04 0 0 1 1.6 1.3 2.04 2.04 0 0 1-.5 2.1l-.6-.6a2.08 2.08 0 0 1-1.1-1.3v-.3a.55 .55 0 0 0 0-.9 .55 .55 0 0 0-.8 .5l.2 .4a.86 .86 0 0 1-.3-1.4 .53 .53 0 0 0-.5-.7 .53 .53 0 0 0-.4 .8l.1 .2-.6-.7a.6 .6 0 0 0-.3-.7 .6 .6 0 0 0-.7 .1 .62 .62 0 0 0 .5 1l4.1 4.1-.9 .3-1.2 .1a1.24 1.24 0 0 1-.6-1.5l.1-.4a.57 .57 0 0 0 .1-.8 .57 .57 0 0 0-.8 0 .57 .57 0 0 0 .1 .8l.1 .7a1.46 1.46 0 0 1-.6-1.7v-.2a.57 .57 0 0 0 .2-.8 .57 .57 0 0 0-.9-.1 .57 .57 0 0 0 .1 .9 .77 .77 0 0 1-.4-1l-.9-.9a.56 .56 0 0 0-.5-.7 .56 .56 0 0 0-.6 .7 .56 .56 0 0 0 .7 .4 1.51 1.51 0 0 1 .9 1.5l.1 .1a1.36 1.36 0 0 1 .7 1.4l1.5 1.6h-5.7a3.5 3.5 0 0 1-2.7-.6 2.19 2.19 0 0 1 1-3.7z"/>
<path d="M130.8 159.7h.2z"/>
<path d="M131.2 157.6l.1 .1z"/>
<path d="M131.2 159.5l.2 .4h-.2z"/>
<path d="M131.7 159.6h.2l.1 .3h-.4l.1-.2h.1h-.1z"/>
<path d="M131.7 156.8h.1l.2-.2-.2 .3z"/>
<path d="M130.8 158.1h1v.2h-.6v.2h.6v.3h-.6v.2h.6v.3h-1z"/>
<path d="M131.3 156.5l1-.7-.3 .2a1.04 1.04 0 0 0-.8 .9l.5 .3v.5h.5l-.6 .1v-.6l-.2 .2 .2-.2h-.2a.27 .27 0 0 0-.3 .2 .27 .27 0 0 0 .1 .3h.2a.27 .27 0 0 1-.3 0 .27 .27 0 0 1-.1-.3 .31 .31 0 0 0 .3-.3 .31 .31 0 0 0-.2-.3z"/>
<path d="M131.8 156.9l.1 .6z"/>
<path d="M132 159.6h.3h-.2l.2 .2h-.3h.2z"/>
<path d="M132.3 156.2l.1 .2z"/>
<path d="M132.4 156.5v.2z"/>
<path d="M132.4 156.4l.1 .4z"/>
<path d="M132.4 159.6l.2-.1-.1 .1 .1 .1a.15 .15 0 0 1-.1 .2 .15 .15 0 0 1-.1-.1h.2z"/>
<path d="M132.4 156l.2 .2h-.2h.2z"/>
<path d="M132.1 156.3l.1 .1a.9 .9 0 0 0 .4 1.1l.1 .3-.2-.1v-.3a.85 .85 0 0 1-.4-1z"/>
<path d="M132 158.1h.3l.3 .8 .3-.8h.4l-.5 1.2a.45 .45 0 0 1-.4-.1 .45 .45 0 0 1-.2-.5z"/>
<path d="M132.5 155.8l.1 .4z"/>
<path d="M132.6 157.2l.1 .1z"/>
<path d="M132.8 157.7l-.1 .1z"/>
<path d="M132.7 157.5l.1 .1z"/>
<path d="M132.8 159.6a.18 .18 0 0 1 .3 0 .18 .18 0 0 1-.1 .3 .18 .18 0 0 1-.3-.2h.3l-.1-.1-.2 .1z"/>
<path d="M132.4 156.8l.6 .6-.4-.3v.1z"/>
<path d="M133 157.2v.1z"/>
<path d="M133.3 159.5l.3 .1v.3l-.2-.2-.1 .2v-.3h.2z"/>
<path d="M133.8 157.1l-.1 .2z"/>
<path d="M133.9 157l-.1 .1z"/>
<path d="M133.8 159.6v-.1a.18 .18 0 0 1 .2 .2 .18 .18 0 0 1-.1 .2 .18 .18 0 0 1-.2-.2h.2l-.1-.1-.1 .1z"/>
<path d="M134.3 155v.1a1.36 1.36 0 0 0-.2 1.3l-.2-.7z"/>
<path d="M133.5 158.2a.65 .65 0 0 1 1.1 .1 .65 .65 0 0 1-.5 1 .65 .65 0 0 1-.7-.7h.3v.1a.27 .27 0 0 0 .4 .3 .27 .27 0 0 0 .1-.4 .26 .26 0 0 0-.2-.2 .26 .26 0 0 0-.3 .2h-.3z"/>
<path d="M133.8 155.1a.74 .74 0 0 1 .8-.3v-.1h-.3h.1a.28 .28 0 0 1 .3-.2 .28 .28 0 0 1 .2 .3l-.1-.1-.1 .1 .2 .3-.3-.1a.33 .33 0 0 0-.3-.2 .33 .33 0 0 0-.3 .2l-.1 .1a.87 .87 0 0 0 0 1.3 .52 .52 0 0 1 .2 .7l.1 .7h-.2v-.9a.37 .37 0 0 0-.4 .1 .37 .37 0 0 0-.1 .4v.3h-.1l.2-1h.4h-.4l-.2-.4 .6 .4-.6-.4v-.3z"/>
<path d="M134.1 159.5l.3 .1v.2l-.3 .1v-.1h.2h-.2v-.2h.2z"/>
<path d="M134.4 155.5l-.2 .8a.56 .56 0 0 1 .2-.8z"/>
<path d="M134.2 156.3v.2z"/>
<path d="M134.3 157.2v.2z"/>
<path d="M134.2 156.3l.1 .1z"/>
<path d="M134.3 157v.1z"/>
<path d="M134.3 157.5l.1 .1z"/>
<path d="M134.5 159.6a.18 .18 0 0 1 .3 0 .18 .18 0 0 1-.1 .3 .18 .18 0 0 1-.2-.2l.2 .1v-.2z"/>
<path d="M134.9 159.6h.3l-.1 .3z"/>
<path d="M135.2 157.3v.3z"/>
<path d="M135.3 159.5v.4z"/>
<path d="M135.4 157.1l.1-.1z"/>
<path d="M135.5 159.6a.21 .21 0 0 1 .2 0 .21 .21 0 0 1 .1 .2h-.3l-.1-.1h.3l-.1-.1-.2 .1z"/>
<path d="M135.7 156l.1 .1z"/>
<path d="M134.8 158.1h.4v.9h.6v.3l-1-.1z"/>
<path d="M135.8 155v.1z"/>
<path d="M135.8 155.2v.2l.1-.1-.1 .3z"/>
<path d="M135.8 156.1l.1 .1z"/>
<path d="M135.9 155.1v.1z"/>
<path d="M136.1 157.4v.1z"/>
<path d="M135.9 156.3l.2 .2z"/>
<path d="M135.9 159.6l.1 .2 .1-.3a.19 .19 0 0 1 .1 .3 .19 .19 0 0 1-.3 0 .19 .19 0 0 1 0-.2z"/>
<path d="M136.2 156v.3z"/>
<path d="M136.1 156.5l.1 .3z"/>
<path d="M135.7 154.5a.32 .32 0 0 1 .5 .2l-.1-.2v.1l.1 .3h-.2l-.1-.3v.2h-.3a.71 .71 0 0 0 0 .8 .71 .71 0 0 0 .7 .3l.2 .1-.7-.1-.3-.2-.1-.5-.1 .6a.56 .56 0 0 0 .5 .7 .46 .46 0 0 1 .1 .7 .4 .4 0 0 0 .1 .5 .4 .4 0 0 0 .5 0l-.7 .1 .1-1-.1-.2-.1 .2a.78 .78 0 0 0-.7 .8l.3 .1a.33 .33 0 0 1-.4-.2 .33 .33 0 0 1 .2-.4l.1-.2a.24 .24 0 0 0 .2-.1 .24 .24 0 0 0-.1-.3l.4 .1-.4-.1-.1-.1 .3 .1v-.1a.57 .57 0 0 1-.4-.7l-.1-.3 .2 .4 .1-.6-.3 .2z"/>
<path d="M136.4 155.8h.1z"/>
<path d="M136.3 159.5l.3 .1h-.2l.1 .1-.1 .1 .2 .1h-.3z"/>
<path d="M136 158.1h.3l.1 .8a.21 .21 0 0 0 .2 .1 .21 .21 0 0 0 .1-.2l.1-.7h.3v.4a.6 .6 0 0 1-.6 .8 .6 .6 0 0 1-.5-.8z"/>
<path d="M136.9 159.5l.3 .1h-.1l.1 .1-.1 .1 .1 .1h-.3z"/>
<path d="M137.3 155.4v.2z"/>
<path d="M137.3 157.3v.1z"/>
<path d="M137.4 155.1l-.1 .1z"/>
<path d="M137.3 157.1v.1z"/>
<path d="M137.4 157v.1z"/>
<path d="M137.4 154.9v.1z"/>
<path d="M137.3 159.5l.3 .2-.2 .2-.1-.3h.2z"/>
<path d="M137.3 155.8l.1 .1z"/>
<path d="M137.7 155.3v.3z"/>
<path d="M137.6 155.8h.1z"/>
<path d="M137.7 159.5v.4z"/>
<path d="M138 156.7v.5z"/>
<path d="M137.9 159.6h.3l-.2 .3z"/>
<path d="M137.3 158.1h1.2v.3h-.4v.9h-.4v-.9h-.4z"/>
<path d="M130.8 158h12.6z"/>
<path d="M136.2 153.6l1 .7h.3h-.3a.3 .3 0 0 1 .3-.3 .3 .3 0 0 1 .3 .3l-.2-.2v.3l.2 .1a.3 .3 0 0 0 .2 .5l.1-.1 .6 .6-.6-.5-.4 .2v-.4v.3l.3-.1-.4-.3-.1-.3a1.12 1.12 0 0 0-.1 1.7v.2l.3 .4 .1 1.1h.5h-.6l-.1-1.2a.7 .7 0 0 0-.4 1l-.1 .1 .4 .1h-.5v-.7l.2-.5h.3h-.3v-.3h.2l.1 .2-.1-.2h-.2v-.1a1.72 1.72 0 0 1 0-1.7v-.1h.6h-.6z"/>
<path d="M138.3 159.6l.2 .3-.3-.1v-.1h.2h-.2z"/>
<path d="M138.8 159.5l-.1 .4z"/>
<path d="M139 159.5l.3 .1h-.2l.2 .1-.2 .1 .2 .1h-.3z"/>
<path d="M139.4 159.5l.3 .1-.3 .3v-.3h.2h-.2z"/>
<path d="M139.3 153.6h.4l.1 .1h-.3l-.1 .4-.1-.2z"/>
<path d="M139.5 154.4v.1z"/>
<path d="M139.4 154.6l.3 .7-.2 .1-.1-.6z"/>
<path d="M138.7 158.1h1v.2h-.6v.2h.6v.3h-.6v.2h.6v.3h-1z"/>
<path d="M139.6 154.2l.1-.1 .1 .4-.1 .9z"/>
<path d="M139.8 159.5v.4z"/>
<path d="M139.7 155.6l.3 .4z"/>
<path d="M139.9 159.6h.3l-.1 .3z"/>
<path d="M140.2 155.7l.1 1-.3-.6 .1 .1z"/>
<path d="M140.3 156.8v.2z"/>
<path d="M140.3 157.1v.2z"/>
<path d="M140.3 157.4v.1z"/>
<path d="M140.3 159.5l.3 .1h-.2l.2 .1-.2 .1 .2 .1h-.3z"/>
<path d="M139.3 154.1l-.1 .9 .2 .8h.1v-.3h.2l-.1 .1a2.08 2.08 0 0 1 .6 2l.5 .3h-.7l-.1-1.3-.3-.2-.1 .4-.5 .6h-.1l.2 .3a.41 .41 0 0 1-.5-.4l.4-.4h.4l.2-.3v-.3l-.3 .6h-.3l.2-.3v-1.3a.89 .89 0 0 1 .1-1.1z"/>
<path d="M140.9 153.3l-.1 .4z"/>
<path d="M140.7 159.6h.2l-.1 .1 .2 .1a.18 .18 0 0 1-.3 0 .18 .18 0 0 1 0-.2z"/>
<path d="M139.9 158.1h.4v.4l.1-.1a.55 .55 0 0 1 .8-.3l-.1 .2a.32 .32 0 0 0-.3 .2 .32 .32 0 0 0 .2 .4l.2 .3-.1 .1a.47 .47 0 0 1-.6-.5l-.2 .2v.3l-.4-.1z"/>
<path d="M141 153.5h.1z"/>
<path d="M141.1 159.6l.1 .1 .2-.1v.2l-.2-.1-.1 .2z"/>
<path d="M140.9 153.9v.3a.29 .29 0 0 0 .2 .5v-.5l.2 .4a.53 .53 0 0 1-.2 .8l.2 .1-.1 .1-.1 .7 .3-.1-.2 1.2 .1-1a.16 .16 0 0 0-.3 .1 .16 .16 0 0 0 .2 .2h-.1l-.1 1.1h.6l-.6 .1v-2.6a.4 .4 0 0 0 .2-.6 .2 .2 0 0 1-.3 .1 .2 .2 0 0 1-.1-.3z"/>
<path d="M141.3 154.1l.1 .2z"/>
<path d="M141.4 156v.1z"/>
<path d="M141.2 153.5l.5 .4-.1 .1-.4-.3 .2 .3-.1 .1v.3l.3 .6 .2 .1-.3-.1v.5l-.1 .1v-.1h.1v-.4l-.3-.9 .1-.2z"/>
<path d="M141.4 155.8v.1z"/>
<path d="M141.3 153.7l.1 .3z"/>
<path d="M141.4 154l.1 .4-.1-.1z"/>
<path d="M141.4 153.5l.1 .1z"/>
<path d="M141.5 153.6l.1 .1z"/>
<path d="M141.7 159.5l-.1 .4z"/>
<path d="M141.6 154.2l.1 .7z"/>
<path d="M142 159.5v.4z"/>
<path d="M141.9 154.6l1.1-.6-.9 .6z"/>
<path d="M142.1 159.5l.3 .1-.2 .3-.1-.3h.2z"/>
<path d="M141.4 158.6l.9-.4v.3l-.5 .2 .5 .2v.3l-.9-.4z"/>
<path d="M142.2 154.7l1.1-.8v.2l-.5 .3a.42 .42 0 0 0-.5 .4l.2-.1-.2 .2z"/>
<path d="M142.5 159.6h.2h-.1l.2 .2h-.3h.2z"/>
<path d="M142.9 159.6l.3 .3h-.4l.1-.2h.1h-.1z"/>
<path d="M142.5 158.6l.9-.4a.3 .3 0 0 1 0 .3 .3 .3 0 0 1-.4 .1l-.1 .1 .6 .2v.3l-1-.4z"/>
<path d="M143.4 159.7h.1z"/>
<path d="M59 79.6a1.02 1.02 0 0 1 1.1-.3 1.02 1.02 0 0 1 .6 1h-2z"/>
<path d="M58.7 80.8h2v1h-2z"/>
<path d="M58.7 82.3h2a1.02 1.02 0 0 1-1 1 1.02 1.02 0 0 1-1-1z"/>
<path d="M74.1 186.6h.8v.2h-.8z"/>
<path d="M74.1 189.1h.8v.3h-.8z"/>
<path d="M74.1 191.6h.8v.3h-.8z"/>
<circle cx="136.5" cy="166.3" r=".32"/>
<circle cx="138.4" cy="166.3" r=".31"/>
<circle cx="138.6" cy="167.8" r=".31"/>
<circle cx="139.7" cy="169" r=".32"/>
<circle cx="139.9" cy="166.7" r=".3"/>
<circle cx="141" cy="167.8" r=".31"/>
</g>
<path d="M67.6 74.9h2v5.1h-2zM70.1 74.9h2v5.1h-2z" fill="none" stroke="#9c9b98" stroke-width=".25"/>
<path d="M68.6 73.7v1.2M71.1 73.7v1.2M68.6 80v1.3M71.1 80v1.3" fill="none" stroke="#9c9b98" stroke-width=".18"/>
<path d="M67 73.9l3.2 7.2M69.5 73.9l3.2 7.2M70.2 73.9l-3.2 7.2M72.7 73.9l-3.2 7.2" fill="none" stroke="#e12e31" stroke-width=".46"/>
<path d="M172 26.2h4M172 24.6h4" fill="none" stroke="#840000" stroke-width=".51"/>
<path d="M101.6 39.4h20.3v45.7h-20.3z" fill="#ffffc2"/>
<path d="M101.6 39.4h20.3v45.7h-20.3zM166.6 58.4h2.1v5.1h-2.1zM82.8 76.2h2v5.1h-2zM81.3 161.3h2.5l-1.3 2.5zM81.3 163.8h2.5M81.5 167.6h2.1v5.1h-2.1zM91.4 161.3h2.6l-1.3 2.5zM91.4 163.8h2.6M91.7 167.6h2v5.1h-2z" fill="none" stroke="#840000" stroke-width=".25"/>
<g fill="none" stroke="#840000" stroke-width=".18">
<path d="M109.2 36.8v2.6M111.8 36.8v2.6M114.3 36.8v2.6M99.1 41.9h2.5M99.1 47h2.5M99.1 49.5h2.5M99.1 54.6h2.5M99.1 57.2h2.5M99.1 59.7h2.5M121.9 41.9h2.6M121.9 47h2.6M121.9 49.5h2.6"/>
<path d="M121.9 54.6h2.6M121.9 57.2h2.6M121.9 59.7h2.6M121.9 44.5h2.6M121.9 52.1h2.6M149.9 49.5h.1M149.9 47l-.8 1.3M149.9 47l.7 1.3M149.9 47v2.5M167.6 57.2v1.2M83.8 74.9v1.3M99.1 62.2h2.5"/>
<path d="M99.1 64.8h2.5M99.1 67.3h2.5M99.1 69.9h2.5M121.9 62.2h2.6M121.9 64.8h2.6M121.9 67.3h2.6M121.9 69.9h2.6M121.9 72.4h2.6M121.9 74.9h2.6M121.9 77.5h2.6M167.6 64.8v1.2h1.3l-1.3 1.3-1.2-1.3h1.2M167.6 64.8h.1"/>
<path d="M167.6 63.5v1.3M83.8 81.3v1.3M111.8 85.1v2.5M114.3 85.1v2.5M121.9 80h2.6M158.7 87.6h.1M158.7 85.1l-.7 1.3M158.7 85.1l.8 1.3M158.7 85.1v2.5M268 87.6h4.2M268 90.2h4.2M268 92.7h4.2"/>
<path d="M268 95.3h4.2M82.5 158.8h.1M82.5 156.2l-.7 1.3M82.5 156.2l.8 1.3M82.5 156.2v11.4M92.7 158.8h.1M92.7 156.2l-.8 1.3M92.7 156.2l.8 1.3M92.7 156.2v11.4M257.8 141v1.2h1.3l-1.3 1.3-1.3-1.3h1.3M257.8 141h.1M82.5 174v1.3h1.3l-1.3 1.2-1.2-1.2h1.2"/>
<path d="M82.5 174h.1M82.5 172.7v1.3M83.3 165.6l1.5 1.5v-.7v.7h-.7M83.3 164.3l1.5 1.6v-.8v.8h-.7M92.7 172.7v1.3M93.5 165.6l1.5 1.5v-.7v.7h-.8M93.5 164.3l1.5 1.6v-.8v.8h-.8M134.9 191.5h2a1.02 1.02 0 0 1-1 1 1.02 1.02 0 0 1-1-1zM135.2 188.8a1.02 1.02 0 0 1 1.1-.3 1.02 1.02 0 0 1 .6 1h-2zM135.9 185.4v3.1M135.9 192.5v3.1M136.9 190.5h2.8"/>
<path d="M156.5 191.5h2a1.02 1.02 0 0 1-1 1 1.02 1.02 0 0 1-1-1zM156.8 188.8a1.02 1.02 0 0 1 1.1-.3 1.02 1.02 0 0 1 .6 1h-2zM157.5 185.4v3.1M157.5 192.5v3.1M158.5 190.5h2.8"/>
</g>
<path d="M123.4 56.7h.8M100.6 69.4h.7M123.4 69.4h.8" fill="none" stroke="#a90000" stroke-width=".18"/>
<path d="M151.6 45h.6M120.3 70.4h.8M131.5 89.9l.6 .8M132.1 89.9l-.6 .8M160.4 83.1h.5l.2 .3-.1 .3-.6 .1M84.1 153l.2 .2v.3l-.2 .1M95.4 153l-.4 1.2" fill="none" stroke="#006464" stroke-width=".18"/>
<g fill="#840000" stroke="#840000" stroke-width=".18">
<path d="M272.2 87.5h.8v.3h-.8z"/>
<path d="M272.2 90h.8v.3h-.8z"/>
<path d="M272.2 92.6h.8v.2h-.8z"/>
<path d="M272.2 95.1h.8v.3h-.8z"/>
<path d="M156.8 188.8a1.02 1.02 0 0 1 1.1-.3 1.02 1.02 0 0 1 .6 1h-2z"/>
<path d="M156.5 190h2v1h-2z"/>
<path d="M156.5 191.5h2a1.02 1.02 0 0 1-1 1 1.02 1.02 0 0 1-1-1z"/>
<path d="M135.2 188.8a1.02 1.02 0 0 1 1.1-.3 1.02 1.02 0 0 1 .6 1h-2z"/>
<path d="M134.9 190h2v1h-2z"/>
<path d="M134.9 191.5h2a1.02 1.02 0 0 1-1 1 1.02 1.02 0 0 1-1-1z"/>
</g>
<path d="M264.2 132.1h5v7.6h-5z" fill="#ffffc2"/>
<path d="M264.2 132.1h5v7.6h-5zM101.6 161.3h2.5l-1.2 2.5zM101.6 163.8h2.5M101.9 167.6h2v5.1h-2zM114.3 161.3h2.5l-1.2 2.5zM114.3 163.8h2.5M114.6 167.6h2v5.1h-2z" fill="none" stroke="#840000" stroke-width=".25"/>
<g fill="none" stroke="#840000" stroke-width=".18">
<path d="M29.2 58.4v1.3h1.3l-1.3 1.3-1.3-1.3h1.3M29.2 58.4h.1M260.3 133.4h3.9M260.3 135.9h3.9M260.3 138.4h3.9M264.2 133.2h1.2v.3h-1.2zM264.2 135.8h1.2v.2h-1.2zM264.2 138.3h1.2v.3h-1.2zM268 133.2h1.2v.3h-1.2zM268 135.8h1.2v.2h-1.2zM268 138.3h1.2v.3h-1.2zM269.2 133.4h3.8"/>
<path d="M269.2 135.9h3.8M269.2 138.4h3.8M102.9 158.8v8.8M115.6 158.8v8.8M102.9 172.7v1.3M103.6 165.6l1.6 1.5v-.7v.7h-.8M103.6 164.3l1.6 1.6v-.8v.8h-.8M115.6 172.7v1.3M116.3 165.6l1.6 1.5v-.7v.7h-.8M116.3 164.3l1.6 1.6v-.8v.8h-.8M104.1 193v1.3h1.3l-1.3 1.3-1.2-1.3h1.2M104.1 193h.1"/>
<path d="M104.1 190.5v2.5M109.2 190.5v2.5M114.3 190.5v2.5M119.4 190.5v2.5"/>
</g>
<g fill="none" stroke="#840000" stroke-width="1.3">
<circle cx="104.1" cy="189.2" r="1.27"/>
<circle cx="109.2" cy="189.2" r="1.27"/>
<circle cx="114.3" cy="189.2" r="1.27"/>
<circle cx="119.4" cy="189.2" r="1.27"/>
</g>
<path d="M108.2 169.5h.8" fill="none" stroke="#006464" stroke-width=".18"/>
<path d="M41.9 74.9h5.1v7.7h-5.1z" fill="#ffffc2"/>
<path d="M174.2 58.4h2.1v5.1h-2.1zM181.9 58.4h2v5.1h-2zM41.9 74.9h5.1v7.7h-5.1z" fill="none" stroke="#840000" stroke-width=".25"/>
<g fill="none" stroke="#840000" stroke-width=".18">
<path d="M175.3 57.2v1.2M182.9 57.2v1.2M38.1 76.2h3.8M38.1 78.7h3.8M41.9 76.1h1.3v.2h-1.3zM41.9 78.6h1.3v.3h-1.3zM45.7 76.1h1.3v.2h-1.3zM45.7 78.6h1.3v.3h-1.3zM47 76.2h3.8M47 78.7h3.8M175.3 63.5v1.3M182.9 63.5v1.3"/>
<path d="M33 83.8v1.3l1 .6-1 .7-1-.7 1-.6M33 83.8h.1M35.6 83.8v1.3h1.2l-1.2 1.3-1.3-1.3h1.3M35.6 83.8h.1M38.1 81.3h3.8M41.9 81.2h1.3v.2h-1.3zM45.7 81.2h1.3v.2h-1.3zM47 81.3h3.8M191.8 87.6h.1M191.8 85.1l-.8 1.3M191.8 85.1l.7 1.3M191.8 85.1v2.5"/>
</g>
<path d="M43.3 72.1v.9M43.3 72.8l-.2 .2M44.3 72.2l-.3-.1-.2 .2 .1 .2 .4 .1v.3h-.5M53.2 71.7l.3 .1M53.5 72.8l-.3 .2M193.4 83.1h.5l.3 .3-.2 .3-.6 .1" fill="none" stroke="#006464" stroke-width=".18"/>
<path d="M221 111.8h2.5v5h-2.5z" fill="#ffffc2"/>
<path d="M228.6 51.1h5.1v2h-5.1zM228.6 53.6h5.1v2h-5.1zM228.6 56.1h5.1v2.1h-5.1zM228.6 58.7h5.1v2h-5.1zM228.6 48.5h5.1v2h-5.1zM85.3 76.2h2.1v5.1h-2.1zM221 111.8h2.5v5h-2.5z" fill="none" stroke="#840000" stroke-width=".25"/>
<g fill="none" stroke="#840000" stroke-width=".18">
<path d="M227.3 52.1h1.3M227.3 54.6h1.3M227.3 57.2h1.3M227.3 59.7h1.3M227.3 49.5h1.3M233.7 52.1h1.2M233.7 54.6h1.2M233.7 57.2h1.2M233.7 59.7h1.2M233.7 49.5h1.2M86.4 74.9v1.3M86.4 81.3v1.3"/>
<path d="M257.8 87.6h.1M257.8 85.1l-.8 1.3M257.8 85.1l.8 1.3M257.8 85.1v2.5M222.1 111.8h.3v1.2h-.3zM222.1 115.6h.3v1.2h-.3zM222.2 108v3.8M222.2 116.8v3.9M27.9 158.8h.1M27.9 156.2l-.7 1.3M27.9 156.2l.8 1.3M27.9 156.2v2.6"/>
<path d="M27.9 171.5v1.2h1.3l-1.3 1.3-1.2-1.3h1.2M27.9 171.5h.1M25.4 186.7h4.2M25.4 189.2h4.2M25.4 191.8h4.2M31.7 186.7h4.3M31.7 189.2h4.3M31.7 191.8h4.3M38.1 186.7h4.2M38.1 189.2h4.2M38.1 191.8h4.2M44.4 186.7h4.3"/>
<path d="M44.4 189.2h4.3M44.4 191.8h4.3M76.2 186.7h4.2M76.2 189.2h4.2M76.2 191.8h4.2"/>
</g>
<path d="M226.9 53.9h.8M259.5 83.1h.5l.2 .3-.1 .3-.6 .1M30.7 153l-.5 1.2" fill="none" stroke="#006464" stroke-width=".18"/>
<g fill="#840000" stroke="#840000" stroke-width=".18">
<path d="M42.3 186.6h.9v.2h-.9z"/>
<path d="M42.3 189.1h.9v.3h-.9z"/>
<path d="M42.3 191.6h.9v.3h-.9z"/>
<path d="M80.4 186.6h.9v.2h-.9z"/>
<path d="M80.4 189.1h.9v.3h-.9z"/>
<path d="M80.4 191.6h.9v.3h-.9z"/>
<path d="M48.7 186.6h.8v.2h-.8z"/>
<path d="M48.7 189.1h.8v.3h-.8z"/>
<path d="M48.7 191.6h.8v.3h-.8z"/>
<path d="M36 186.6h.8v.2h-.8z"/>
<path d="M36 189.1h.8v.3h-.8z"/>
<path d="M36 191.6h.8v.3h-.8z"/>
<path d="M29.6 186.6h.9v.2h-.9z"/>
<path d="M29.6 189.1h.9v.3h-.9z"/>
<path d="M29.6 191.6h.9v.3h-.9z"/>
</g>
<path d="M41.9 154.9h5.1v17.8h-5.1z" fill="#ffffc2"/>
<g fill="none" stroke="#840000" stroke-width=".25">
<path d="M228.6 43.4h5.1v2.1h-5.1zM228.6 46h5.1v2h-5.1zM228.6 40.9h5.1v2h-5.1zM103.1 121.3v3.8M103.6 120.9v1M103.6 122.7v1M103.6 124.5v1M41.9 154.9h5.1v17.8h-5.1z"/>
<circle cx="104.5" cy="123.2" r="2.79"/>
</g>
<g fill="none" stroke="#840000" stroke-width=".18">
<path d="M55.9 48.3h.1M55.9 45.7l-.8 1.3M55.9 45.7l.7 1.3M55.9 45.7v5.4M55.9 53.1v2.8M227.3 44.5h1.3M227.3 47h1.3M227.3 41.9h1.3M233.7 44.5h1.2M233.7 47h1.2M233.7 41.9h1.2M86.4 74.9h.1"/>
<path d="M86.4 72.4l-.8 1.3M86.4 72.4l.7 1.3M86.4 72.4v2.5M96.5 87.6v1.3h1.3l-1.3 1.3-1.3-1.3h1.3M96.5 87.6h.1M105.4 118.1v3.3M97.8 123.2h5.3M103.6 121.4h2.6v3.6h-2.6M103.6 123.2h1.8v5.1M105.8 122.8h.8M106.2 122.8l.4 .6h-.8zM38.1 156.2h3.8"/>
<path d="M38.1 158.8h3.8M41.9 156.1h1.3v.2h-1.3zM41.9 158.6h1.3v.3h-1.3zM45.7 156.1h1.3v.2h-1.3zM45.7 158.6h1.3v.3h-1.3zM47 156.2h3.8M47 158.8h3.8M38.1 161.3h3.8M38.1 163.8h3.8M38.1 166.4h3.8M38.1 168.9h3.8M38.1 171.5h3.8"/>
<path d="M41.9 161.2h1.3v.2h-1.3zM41.9 163.7h1.3v.3h-1.3zM41.9 166.2h1.3v.3h-1.3zM41.9 168.8h1.3v.2h-1.3zM41.9 171.3h1.3v.3h-1.3zM45.7 161.2h1.3v.2h-1.3zM45.7 163.7h1.3v.3h-1.3zM45.7 166.2h1.3v.3h-1.3zM45.7 168.8h1.3v.2h-1.3zM45.7 171.3h1.3v.3h-1.3zM47 161.3h3.8M47 163.8h3.8"/>
<path d="M47 166.4h3.8M47 168.9h3.8M47 171.5h3.8M16.5 189.2h.1M16.5 191.8v1.2h1.3l-1.3 1.3-1.3-1.3h1.3M16.5 191.8h.1M16.5 186.7l-.8 1.3M16.5 186.7l.8 1.3M16.5 186.7v2.5"/>
</g>
<path d="M40.2 168.5h.8" fill="none" stroke="#a90000" stroke-width=".18"/>
<path d="M58.6 42.5l-.4 1.3M64.9 53.3h.4M64.9 52.6h.6M89.1 69.2l-.4 1.2M18.2 184.7h.5l.2 .3-.1 .3-.6 .1" fill="none" stroke="#006464" stroke-width=".18"/>
<g fill="#840000" stroke="#840000" stroke-width=".18">
<path d="M103.9 123.2l1-.4v.8z"/>
<circle cx="105.4" cy="121.4" r=".25"/>
<circle cx="105.4" cy="125" r=".25"/>
</g>
<path d="M53.8 51.3h4.1M53.8 52.8h4.1" fill="none" stroke="#840000" stroke-width=".51"/>
<path d="M38.1 45.7h10.2v10.2h-10.2z" fill="#ffffc2"/>
<path d="M38.1 45.7h10.2v10.2h-10.2z" fill="none" stroke="#840000" stroke-width=".25"/>
<path d="M44.7 28.2h4.6v.5h-4.6zM47 25.4v2.8M47 30.2v2.8M47.8 26.9h1M48.3 26.4v1M35.6 48.3h2.5M35.6 50.8h2.5M43.2 55.9v2.5M48.3 48.3h2.5" fill="none" stroke="#840000" stroke-width=".18"/>
<path d="M43.6 30.4h.4M43.6 29.8h.6M49.7 42.6l.2-.1a.68 .68 0 0 1 .4 .6 .68 .68 0 0 1-.4 .7 .84 .84 0 0 1-.2-1.2z" fill="none" stroke="#006464" stroke-width=".18"/>
<path d="M44.7 29.7h4.6v.5h-4.6z" fill="#840000" stroke="#840000" stroke-width=".18"/>
<path d="M54.6 17.8h5.1v7.6h-5.1z" fill="#ffffc2"/>
<path d="M54.6 17.8h5.1v7.6h-5.1zM95.5 125.7h2v5.1h-2z" fill="none" stroke="#840000" stroke-width=".25"/>
<g fill="none" stroke="#840000" stroke-width=".18">
<path d="M50.8 19.1h3.8M54.6 18.9h1.3v.3h-1.3zM58.4 18.9h1.3v.3h-1.3zM59.7 19.1h3.8M31.7 20.3l1.1-.6-1.1-.6-1 .6 1 .6v1.3M31.7 21.6h.1M33.3 28.2h4.5v.5h-4.5zM35.6 25.4v2.8M35.6 30.2v2.8M36.3 26.9h1M36.8 26.4v1M50.8 21.6h3.8"/>
<path d="M50.8 24.1h3.8M54.6 21.5h1.3v.2h-1.3zM54.6 24h1.3v.3h-1.3zM58.4 21.5h1.3v.2h-1.3zM58.4 24h1.3v.3h-1.3zM59.7 21.6h3.8M59.7 24.1h3.8M29.2 48.3h.1M29.2 45.7l-.8 1.3M29.2 45.7l.8 1.3M29.2 45.7v5.4M29.2 53.1v2.8"/>
<path d="M259.1 68.6v1.3h1.2l-1.2 1.2-1.3-1.2h1.3M259.1 68.6h.1M259.1 66h.1M259.1 63.5l-.8 1.3M259.1 63.5l.7 1.3M259.1 63.5v2.5M96.5 124.5v1.2M96.5 130.8v1.3"/>
</g>
<path d="M32.1 30.4h.4M32.1 29.8h.6M58.9 26.5l-.3-.1-.2 .2 .1 .2 .4 .1v.3h-.5M30.9 43.8h.6M260.6 61.5l.3 .3-.1 .3-.2 .1" fill="none" stroke="#006464" stroke-width=".18"/>
<path d="M33.3 29.7h4.5v.5h-4.5z" fill="#840000" stroke="#840000" stroke-width=".18"/>
<path d="M27.2 51.3h4M27.2 52.8h4" fill="none" stroke="#840000" stroke-width=".51"/>
<path d="M264.2 110.5h5v7.6h-5z" fill="#ffffc2"/>
<path d="M228.6 38.4h5.1v2h-5.1zM228.6 30.7h5.1v2.1h-5.1zM228.6 33.3h5.1v2h-5.1zM228.6 35.8h5.1v2h-5.1zM228.6 28.2h5.1v2h-5.1zM264.2 110.5h5v7.6h-5z" fill="none" stroke="#840000" stroke-width=".25"/>
<g fill="none" stroke="#840000" stroke-width=".18">
<path d="M29.2 19.1l-.8 1.2M29.2 19.1l.8 1.2M29.2 19.1v2.5M34.3 19.1h.1M34.3 16.5l-.8 1.3M34.3 16.5l.8 1.3M34.3 16.5v2.6M36.8 17.8l1-.7-1-.6-1 .6 1 .7v1.3M36.8 19.1h.1M21.8 28.2h4.6v.5h-4.6zM24.1 24.1h.1M24.1 33v1.3h1.3l-1.3 1.3-1.2-1.3h1.2"/>
<path d="M24.1 33h.1M24.1 21.6l-.7 1.3M24.1 21.6l.8 1.3M24.1 21.6v2.5M24.1 25.4v2.8M24.1 30.2v2.8M24.9 26.9h1M25.4 26.4v1M26.7 22.9l1-.7-1-.6-1 .6 1 .7v1.2M26.7 24.1h.1M29.2 21.6h.1M104.1 25.4v2.8"/>
<path d="M104.1 30.2v2.8M118.1 33v1.3h1.3l-1.3 1.3-1.3-1.3h1.3M118.1 33h.1M118.1 25.4v2.8M118.1 30.2v2.8M227.3 39.4h1.3M227.3 31.8h1.3M227.3 34.3h1.3M227.3 36.8h1.3M227.3 29.2h1.3M233.7 39.4h1.2M233.7 31.8h1.2"/>
<path d="M233.7 34.3h1.2M233.7 36.8h1.2M233.7 29.2h1.2M259.1 38.1h.1M259.1 24.1h.1M259.1 26.7v1.2h1.2l-1.2 1.3-1.3-1.3h1.3M259.1 26.7h.1M259.1 21.6v2.5M259.1 35.6v2.5M259.1 35.6l-.8 1.2M259.1 35.6l.7 1.2M259.1 21.6l-.8 1.3"/>
<path d="M259.1 21.6l.7 1.3M268 21.6h4.2M268 24.1h4.2M268 26.7h4.2M270.5 35.6h4.2M270.5 38.1h4.2M259.1 52.1h.1M259.1 40.6v1.3h1.2l-1.2 1.3-1.3-1.3h1.3M259.1 40.6h.1M259.1 54.6v1.3h1.2l-1.2 1.3-1.3-1.3h1.3M259.1 54.6h.1M259.1 49.5l-.8 1.3"/>
<path d="M259.1 49.5l.7 1.3M259.1 49.5v2.6M270.5 49.5h4.2M270.5 52.1h4.2M270.5 54.6h4.2M270.5 40.6h4.2M33 74.9l1-.6-1-.6-1 .6 1 .6v1.3M33 76.2h.1M270.5 63.5h4.2M270.5 66h4.2M270.5 68.6h4.2M257.8 119.4v1.3h1.3l-1.3 1.2-1.3-1.2h1.3"/>
<path d="M257.8 119.4h.1M260.3 111.8h3.9M260.3 114.3h3.9M260.3 116.8h3.9M264.2 111.6h1.2v.3h-1.2zM264.2 114.2h1.2v.2h-1.2zM264.2 116.7h1.2v.3h-1.2zM268 111.6h1.2v.3h-1.2zM268 114.2h1.2v.2h-1.2zM268 116.7h1.2v.3h-1.2zM269.2 111.8h3.8M269.2 114.3h3.8"/>
<path d="M269.2 116.8h3.8M61 138.4v1.3h1.2l-1.2 1.3-1.3-1.3h1.3M61 138.4h.1M114.3 121.9v2.8M114.3 126.7v2.8"/>
</g>
<path d="M102.1 28.4h4.1M102.1 30h4.1M116.1 28.4h4M116.1 30h4M112.3 125h4M112.3 126.5h4" fill="none" stroke="#840000" stroke-width=".51"/>
<g fill="none" stroke="#006464" stroke-width=".18">
<path d="M25.7 19.6l.2 .3v.3l-.2 .1M30.9 17.1h.5l.2 .2-.1 .4-.6 .1M260.6 19.6l.3 .3-.1 .3-.2 .1M20.7 30.4h.4M20.7 29.8h.6M124.8 28.5h.7M127.1 30.4h.4M127.1 29.8h.6M226.9 28.5h.8M260.6 33.6l.3 .2-.1 .3-.2 .2M260.6 47.6l.3 .2-.1 .3-.2 .1M119.8 128.2h.4"/>
<path d="M119.8 127.6h.6"/>
</g>
<g fill="#840000" stroke="#840000" stroke-width=".18">
<path d="M272.2 21.5h.8v.2h-.8z"/>
<path d="M272.2 24h.8v.3h-.8z"/>
<path d="M272.2 26.5h.8v.3h-.8z"/>
<path d="M274.7 49.4h.9v.3h-.9z"/>
<path d="M274.7 51.9h.9v.3h-.9z"/>
<path d="M274.7 54.5h.9v.2h-.9z"/>
<path d="M274.7 35.4h.9v.3h-.9z"/>
<path d="M274.7 38h.9v.2h-.9z"/>
<path d="M274.7 40.5h.9v.3h-.9z"/>
<path d="M274.7 63.4h.9v.2h-.9z"/>
<path d="M274.7 65.9h.9v.3h-.9z"/>
<path d="M274.7 68.5h.9v.2h-.9z"/>
<path d="M21.8 29.7h4.6v.5h-4.6z"/>
</g>
<path d="M204.5 111.8h2.5v5h-2.5z" fill="#ffffc2"/>
<path d="M204.5 111.8h2.5v5h-2.5z" fill="none" stroke="#840000" stroke-width=".25"/>
<path d="M205.6 111.8h.3v1.2h-.3zM205.6 115.6h.3v1.2h-.3zM205.7 108v3.8M205.7 116.8v3.9" fill="none" stroke="#840000" stroke-width=".18"/>
<path d="M35.6 118.1h20.3v15.3h-20.3z" fill="#ffffc2"/>
<path d="M24.4 113h2v5.1h-2zM35.6 118.1h20.3v15.3h-20.3zM24.4 133.4h2v5h-2z" fill="none" stroke="#840000" stroke-width=".25"/>
<g fill="none" stroke="#840000" stroke-width=".18">
<path d="M95.2 25.4v2.8M95.2 30.2v2.8M30.5 76.2h.1M30.5 73.7l-.8 1.2M30.5 73.7l.7 1.2M30.5 73.7v2.5M158.7 95.3v1.2h1.3l-1.3 1.3-1.2-1.3h1.2M158.7 95.3h.1M158.7 87.6v2.8M158.7 92.5v2.8M168.9 87.6h4.2M168.9 90.2h4.2"/>
<path d="M168.9 92.7h4.2M168.9 95.3h4.2M191.8 95.3v1.2h1.2l-1.2 1.3-1.3-1.3h1.3M191.8 95.3h.1M191.8 87.6v2.8M191.8 92.5v2.8M201.9 87.6h4.2M201.9 90.2h4.2M201.9 92.7h4.2M201.9 95.3h4.2M224.8 87.6h.1M224.8 95.3v1.2h1.3l-1.3 1.3-1.3-1.3h1.3"/>
<path d="M224.8 95.3h.1M224.8 85.1l-.8 1.3M224.8 85.1l.8 1.3M224.8 85.1v5.3M224.8 92.5v2.8M234.9 87.6h4.3M234.9 90.2h4.3M234.9 92.7h4.3M234.9 95.3h4.3M257.8 95.3v1.2h1.3l-1.3 1.3-1.3-1.3h1.3M257.8 95.3h.1M257.8 87.6v2.8"/>
<path d="M257.8 92.5v2.8M25.4 111.8v1.2M25.4 118.1v1.3M33 113v1.3h1.3l-1.3 1.3-1.3-1.3h1.3M33 113h.1M33 105.4h.1M33 102.9v5.3M33 110.2v2.8M33 102.9l-.7 1.2M33 102.9l.8 1.2M45.7 115.6v2.5M151.1 113h.1"/>
<path d="M151.1 115.6v1.2h1.3l-1.3 1.3-1.2-1.3h1.2M151.1 115.6h.1M151.1 110.5l-.7 1.3M151.1 110.5l.8 1.3M151.1 110.5v2.5M160 110.5h4.2M160 113h4.2M160 115.6h4.2M172.7 113h.1M172.7 115.6v1.2h1.3l-1.3 1.3-1.3-1.3h1.3M172.7 115.6h.1M172.7 110.5l-.7 1.3"/>
<path d="M172.7 110.5l.8 1.3M172.7 110.5v2.5M181.6 110.5h4.2M181.6 113h4.2M181.6 115.6h4.2M205.7 108h.1M205.7 105.4l-.7 1.3M205.7 105.4l.8 1.3M205.7 105.4v2.6M24.4 126.7h2a1.02 1.02 0 0 1-1 1.1 1.02 1.02 0 0 1-1-1.1zM24.7 124a1.02 1.02 0 0 1 1.1-.2 1.02 1.02 0 0 1 .6 .9h-2zM25.4 120.7v3"/>
<path d="M25.4 127.8v3M25.4 132.1v1.3M25.4 138.4v1.3M26.4 125.7h2.8M33 123.2h2.6M33 125.7h2.6M33 128.3h2.6M45.7 133.4v2.5M55.9 120.7h2.5M55.9 123.2h2.5M55.9 130.8h2.5M165.1 134.6h.1"/>
<path d="M165.1 132.1l-.8 1.3M165.1 132.1l.8 1.3M165.1 132.1v2.5M205.7 120.7v1.2h1.3l-1.3 1.3-1.2-1.3h1.2M205.7 120.7h.1"/>
</g>
<g fill="none" stroke="#006464" stroke-width=".18">
<path d="M93.1 31.7h.4M93.1 31.1h.6M32.2 71.7h.6M154 92h.6M187.1 92h.6M220.1 92h.6M226.5 83.1h.4l.3 .3-.1 .3-.6 .1M253.1 92h.6M34.7 102.2h.6M41.1 110.3h.5M41.1 109.7h.6M60.6 116.2l-.5-.1-.2 .2v.3l.6 .3 .1 .3-.2 .2h-.5"/>
<path d="M61.9 116.1v1.3l-.8-1.3v1.3M152.7 108.5l.2 .3v.3l-.2 .1M174.3 108.5l.2 .3-.1 .3-.1 .1"/>
</g>
<path d="M93.2 28.4h4.1M93.2 30h4.1M156.7 90.7h4.1M156.7 92.2h4.1M189.7 90.7h4.1M189.7 92.2h4.1M222.8 90.7h4M222.8 92.2h4M255.8 90.7h4M255.8 92.2h4M31 108.5h4.1M31 110h4.1" fill="none" stroke="#840000" stroke-width=".51"/>
<g fill="#840000" stroke="#840000" stroke-width=".18">
<path d="M24.4 126.7h2a1.02 1.02 0 0 1-1 1.1 1.02 1.02 0 0 1-1-1.1z"/>
<path d="M24.4 125.2h2v1h-2z"/>
<path d="M24.7 124a1.02 1.02 0 0 1 1.1-.2 1.02 1.02 0 0 1 .6 .9h-2z"/>
<path d="M206.1 87.5h.9v.3h-.9z"/>
<path d="M206.1 90h.9v.3h-.9z"/>
<path d="M206.1 92.6h.9v.2h-.9z"/>
<path d="M206.1 95.1h.9v.3h-.9z"/>
<path d="M173.1 87.5h.9v.3h-.9z"/>
<path d="M173.1 90h.9v.3h-.9z"/>
<path d="M173.1 92.6h.9v.2h-.9z"/>
<path d="M173.1 95.1h.9v.3h-.9z"/>
<path d="M239.2 87.5h.8v.3h-.8z"/>
<path d="M239.2 90h.8v.3h-.8z"/>
<path d="M239.2 92.6h.8v.2h-.8z"/>
<path d="M239.2 95.1h.8v.3h-.8z"/>
<path d="M164.2 110.4h.9v.2h-.9z"/>
<path d="M164.2 112.9h.9v.3h-.9z"/>
<path d="M164.2 115.4h.9v.3h-.9z"/>
<path d="M185.8 110.4h.9v.2h-.9z"/>
<path d="M185.8 112.9h.9v.3h-.9z"/>
<path d="M185.8 115.4h.9v.3h-.9z"/>
</g>
<path d="M171.4 151.1h5.1v7.7h-5.1z" fill="#ffffc2"/>
<path d="M171.4 151.1h5.1v7.7h-5.1z" fill="none" stroke="#840000" stroke-width=".25"/>
<g fill="none" stroke="#840000" stroke-width=".18">
<path d="M165.1 152.4h.1M165.1 149.9l-.8 1.2M165.1 149.9l.8 1.2M165.1 149.9v2.5M167.6 152.4h3.8M167.6 154.9h3.8M167.6 157.5h3.8M171.4 152.3h1.3v.2h-1.3zM171.4 154.8h1.3v.3h-1.3zM171.4 157.4h1.3v.2h-1.3zM175.3 152.3h1.2v.2h-1.2zM175.3 154.8h1.2v.3h-1.2z"/>
<path d="M175.3 157.4h1.2v.2h-1.2zM176.5 152.4h3.8M176.5 154.9h3.8M176.5 157.5h3.8"/>
</g>
<path d="M176.4 148.3h.1" fill="none" stroke="#006464" stroke-width=".18"/>
<path d="M171.4 133.4h5.1v7.6h-5.1z" fill="#ffffc2"/>
<path d="M171.4 133.4h5.1v7.6h-5.1zM226.3 134.6h2v5.1h-2zM226.3 152.4h2v5.1h-2z" fill="none" stroke="#840000" stroke-width=".25"/>
<g fill="none" stroke="#840000" stroke-width=".18">
<path d="M34.3 19.1h.1M36.8 19.1h.1M207 19.1v5M24.1 24.1h.1M24.1 33h.1M24.1 25.4v2.8M24.1 30.2v2.8M26.7 24.1h.1M29.2 21.6h.1M31.7 21.6h.1M86.4 33h.1M86.4 25.4h.1"/>
<path d="M86.4 25.4v2.8M86.4 30.2v2.8M95.2 25.4v2.8M95.2 30.2v2.8M109.2 36.8v2.6M111.8 36.8v2.6M114.3 36.8v2.6M118.1 33h.1M118.1 25.4h.1M118.1 25.4v2.8M118.1 30.2v2.8M174 35.6v1.2h1.3l-1.3 1.3-1.3-1.3h1.3"/>
<path d="M174 35.6h.1M177.8 34.3h1.3M184.1 34.3h1.3M189.2 34.3h5.1M189.2 26.7h5.1M189.2 29.2h5.1M189.2 31.8h5.1M219.7 34.3h5.1M219.7 26.7h5.1M219.7 29.2h5.1M219.7 31.8h5.1M219.7 36.8h5.1"/>
<path d="M219.7 39.4h5.1M227.3 34.3h1.3M227.3 26.7h1.3M227.3 29.2h1.3M227.3 31.8h1.3M227.3 36.8h1.3M227.3 39.4h1.3M233.7 34.3h1.2M233.7 26.7h1.2M233.7 29.2h1.2M233.7 31.8h1.2M233.7 36.8h1.2"/>
<path d="M233.7 39.4h1.2M29.2 48.3h.1M29.2 48.3v2.8M29.2 53.1v2.8M55.9 48.3h.1M55.9 48.3v2.8M55.9 53.1v2.8M99.1 41.9h2.5M99.1 47h2.5M99.1 49.5h2.5M99.1 54.6h2.5M99.1 57.2h2.5"/>
<path d="M99.1 59.7h2.5M121.9 41.9h2.6M121.9 47h2.6M121.9 49.5h2.6M121.9 54.6h2.6M121.9 57.2h2.6M121.9 59.7h2.6M121.9 44.5h2.6M121.9 52.1h2.6M149.9 49.5h.1M151.1 49.5h5.1M151.1 54.6h5.1"/>
<path d="M151.1 52.1h5.1M161.3 49.5h5.1M161.3 54.6h5.1M161.3 52.1h5.1M167.6 57.2v1.2M189.2 49.5h5.1M189.2 54.6h5.1M189.2 57.2h5.1M189.2 59.7h5.1M189.2 52.1h5.1M219.7 41.9h5.1M219.7 47h5.1"/>
<path d="M219.7 49.5h5.1M219.7 54.6h5.1M219.7 57.2h5.1M219.7 59.7h5.1M219.7 44.5h5.1M219.7 52.1h5.1M227.3 41.9h1.3M227.3 47h1.3M227.3 49.5h1.3M227.3 54.6h1.3M227.3 57.2h1.3M227.3 59.7h1.3"/>
<path d="M227.3 44.5h1.3M227.3 52.1h1.3M233.7 41.9h1.2M233.7 47h1.2M233.7 49.5h1.2M233.7 54.6h1.2M233.7 57.2h1.2M233.7 59.7h1.2M233.7 44.5h1.2M233.7 52.1h1.2M25.4 76.2v2.5M30.5 76.2h.1"/>
<path d="M33 76.2h.1M59.7 76.2v2.5M83.8 74.9v1.3M86.4 74.9h.1M86.4 74.9v1.3M99.1 62.2h2.5M99.1 64.8h2.5M99.1 67.3h2.5M99.1 69.9h2.5M121.9 62.2h2.6M121.9 64.8h2.6M121.9 67.3h2.6"/>
<path d="M121.9 69.9h2.6M121.9 72.4h2.6M121.9 74.9h2.6M121.9 77.5h2.6M167.6 64.8h.1M167.6 63.5v1.3M189.2 62.2h5.1M207 72.4h.1M207 67.3v5.1M219.7 62.2h5.1M219.7 64.8h5.1M25.4 83.8v2.6"/>
<path d="M26.7 81.3h2.5M33 83.8h.1M35.6 83.8h.1M55.9 81.3h2.5M59.7 83.8v2.6M83.8 81.3v1.3M86.4 81.3v1.3M111.8 85.1v2.5M114.3 85.1v2.5M121.9 80h2.6M158.7 95.3h.1M158.7 87.6h.1"/>
<path d="M158.7 87.6v2.8M158.7 92.5v2.8M191.8 95.3h.1M191.8 87.6h.1M191.8 87.6v2.8M191.8 92.5v2.8M224.8 95.3h.1M224.8 87.6h.1M224.8 87.6v2.8M224.8 92.5v2.8M257.8 95.3h.1M257.8 87.6h.1"/>
<path d="M257.8 87.6v2.8M257.8 92.5v2.8M33 113h.1M33 105.4h.1M33 105.4v2.8M33 110.2v2.8M45.7 115.6v2.5M105.4 110.5h.1M105.4 118.1v2.6M205.7 108h.1M205.7 108v3.8M205.7 116.8v3.9"/>
<path d="M257.8 111.8h.1M260.3 111.8h3.9M260.3 114.3h3.9M260.3 116.8h3.9M269.2 111.8h3.8M269.2 114.3h3.8M269.2 116.8h3.8M33 123.2h2.6M33 125.7h2.6M33 128.3h2.6M45.7 133.4v2.5M55.9 130.8h2.5"/>
<path d="M55.9 123.2h2.5M55.9 120.7h2.5M96.5 124.5v1.2M96.5 130.8v1.3M97.8 123.2h2.5M105.4 125.7v2.6M167.6 134.6h3.8M167.6 137.2h3.8M167.6 139.7h3.8M171.4 134.5h1.3v.2h-1.3zM171.4 137h1.3v.3h-1.3zM171.4 139.6h1.3v.2h-1.3z"/>
<path d="M175.3 134.5h1.2v.2h-1.2zM175.3 137h1.2v.3h-1.2zM175.3 139.6h1.2v.2h-1.2zM176.5 134.6h3.8M176.5 137.2h3.8M176.5 139.7h3.8M205.7 120.7h.1M217.2 133.4v2.7M217.2 138.2v2.8M227.3 133.4v1.2M227.3 139.7v1.3M228.6 130.8h.1"/>
<path d="M228.6 128.3v2.5M228.6 128.3l-.8 1.2M228.6 128.3l.8 1.2M231.1 130.8h4.3M231.1 133.4h4.3M231.1 135.9h4.3M257.8 133.4h.1M260.3 133.4h3.9M260.3 135.9h3.9M260.3 138.4h3.9M269.2 133.4h3.8M269.2 135.9h3.8"/>
<path d="M269.2 138.4h3.8M82.5 158.8h.1M82.5 158.8v2.5M92.7 158.8h.1M92.7 158.8v2.5M102.9 158.8v2.5M115.6 158.8v2.5M195.6 157.5v1.3h1.2l-1.2 1.2-1.3-1.2h1.3M195.6 157.5h.1M217.2 141v1.2h1.2l-1.2 1.3-1.3-1.3h1.3M217.2 141h.1M217.2 158.8v1.2h1.2l-1.2 1.3-1.3-1.3h1.3"/>
<path d="M217.2 158.8h.1M217.2 151.1v2.8M217.2 156v2.8M227.3 151.1v1.3M227.3 157.5v1.3M228.6 148.6h.1M228.6 146.1l-.8 1.2M228.6 146.1l.8 1.2M228.6 146.1v2.5M231.1 148.6h4.3M231.1 151.1h4.3M231.1 153.7h4.3"/>
<path d="M82.5 174h.1M82.5 163.8v3.8M82.5 172.7v1.3M92.7 163.8v3.8M92.7 172.7v1.3M102.9 163.8v3.8M102.9 172.7v1.3M115.6 163.8v3.8M115.6 172.7v1.3M104.1 193h.1M104.1 190.5v2.5"/>
</g>
<g fill="none" stroke="#006464" stroke-width=".18">
<path d="M25.7 19.6l.2 .3v.3l-.2 .1M30.9 17.1h.5l.2 .2-.1 .4-.6 .1M20.7 30.4h.4M20.7 29.8h.6M89.1 20.9l-.4 1.3M93.1 31.7h.4M93.1 31.1h.6M120.8 20.9l-.4 1.3M124.8 28.5h.7M127.1 30.4h.4M127.1 29.8h.6M220.1 20.9l-.3 1.3"/>
<path d="M226.9 28.5h.8M30.9 43.8h.6M58.6 42.5l-.4 1.3M64.9 53.3h.4M64.9 52.6h.6M151.6 45h.6M218.1 55.2h.8M226.9 53.9h.8M32.2 71.7h.6M89.1 69.2l-.4 1.2M120.3 70.4h.8M131.5 89.9l.6 .8"/>
<path d="M132.1 89.9l-.6 .8M154 92h.6M160.4 83.1h.5l.2 .3-.1 .3-.6 .1M187.1 92h.6M193.4 83.1h.5l.3 .3-.2 .3-.6 .1M220.1 92h.6M226.5 83.1h.4l.3 .3-.1 .3-.6 .1M253.1 92h.6M259.5 83.1h.5l.2 .3-.1 .3-.6 .1M34.7 102.2h.6M41.1 110.3h.5M41.1 109.7h.6"/>
<path d="M60.6 116.2l-.5-.1-.2 .2v.3l.6 .3 .1 .3-.2 .2h-.5M61.9 116.1v1.3l-.8-1.3v1.3M108.1 104.7l-.4 1.3M259.5 107.3h.6M176.4 130.5h.1M213.5 138.3h.4M213.5 137.7h.6M231.3 126.3l-.4 1.3M240 132.7h.7M243.9 134.4h-.3M259.5 128.8h.6M84.1 153l.2 .2v.3l-.2 .1"/>
<path d="M95.4 153l-.4 1.2M213.5 156.1h.4M213.5 155.5h.6M231.3 144.1l-.4 1.3M243.9 152.1l-.3 .1M108.2 169.5h.8"/>
</g>
<path d="M215.1 136.4h4.1M215.1 137.9h4.1M215.1 154.2h4.1M215.1 155.7h4.1" fill="none" stroke="#840000" stroke-width=".51"/>
<g fill="#840000" stroke="#840000" stroke-width=".18">
<path d="M235.4 148.5h.8v.2h-.8z"/>
<path d="M235.4 151h.8v.3h-.8z"/>
<path d="M235.4 153.5h.8v.3h-.8z"/>
<path d="M235.4 130.7h.8v.2h-.8z"/>
<path d="M235.4 133.2h.8v.3h-.8z"/>
<path d="M235.4 135.8h.8v.2h-.8z"/>
</g>
<path d="M85.3 39.8h3.2M245.3 51.6h.7M168.2 89.7h.7M131.2 116h3.2M55 166.8h3.2" fill="none" stroke="#0f0f0f" stroke-width=".18"/>
<g fill="none" stroke="#009600" stroke-width=".18">
<path d="M34.3 19.1h16.5M47 19.1v6.3M63.5 19.1h2.5v13.9h-41.9M207 19.1h-33v2.5M29.2 21.6h21.6M35.6 21.6v3.8M50.8 24.1h-26.7v1.3M63.5 24.1h2.5M63.5 21.6h2.5M86.4 33h17.7M86.4 25.4h25.4v11.4M109.2 25.4v11.4"/>
<path d="M118.1 25.4h-3.8v11.4M174 34.3h3.8M174 29.2v6.4M174 31.8h15.2M180.3 29.2h8.9M180.3 26.7h8.9M185.4 34.3h3.8M234.9 34.3h11.5M234.9 31.8h11.5M234.9 29.2h11.5M234.9 26.7h11.5M234.9 39.4h11.5"/>
<path d="M234.9 36.8h11.5M259.1 24.1h8.9M259.1 26.7h8.9M259.1 38.1h11.4M262.9 21.6h5.1M264.2 35.6h6.3M29.2 55.9v2.5h26.7v-2.5M29.2 48.3h6.4M33 48.3v2.5h2.6M50.8 48.3h5.1M85.1 54.6h14M85.1 41.9h14"/>
<path d="M124.5 54.6h13.9M124.5 52.1h13.9M124.5 47h13.9M124.5 41.9h13.9M124.5 49.5h13.9M124.5 59.7h13.9M124.5 44.5h13.9M149.9 52.1h1.2M151.1 49.5h-1.2v5.1h1.2M166.4 54.6h22.8M166.4 52.1h22.8M166.4 49.5h22.8"/>
<path d="M167.6 49.5v7.7M175.3 52.1v5.1M182.9 54.6v2.6M189.2 57.2v7.6h-21.6M234.9 54.6h11.5M234.9 52.1h11.5M234.9 47h11.5M234.9 41.9h11.5M234.9 49.5h11.5M234.9 57.2h11.5M234.9 59.7h11.5M234.9 44.5h11.5"/>
<path d="M259.1 54.6h11.4M259.1 52.1h11.4M259.1 40.6h11.4M264.2 49.5h6.3M25.4 69.9v6.3M30.5 76.2h7.6M38.1 78.7h-2.5v5.1h-2.6M50.8 78.7h5.1M59.7 69.9v6.3M68.6 72.4v1.3h2.5M83.8 74.9h2.6M85.1 64.8h14"/>
<path d="M85.1 62.2h14M85.1 67.3h14M96.5 77.5v10.1h17.8M96.5 69.9h2.6M124.5 64.8h13.9M124.5 62.2h13.9M124.5 77.5h13.9M124.5 67.3h13.9M124.5 69.9h13.9M124.5 74.9h13.9M259.1 66h11.4M259.1 68.6h11.4"/>
<path d="M264.2 63.5h6.3M25.4 86.4v8.9M29.2 81.3h8.9M50.8 81.3h5.1M59.7 86.4v8.9M68.6 81.3v8.9M71.1 81.3v8.9M83.8 82.6v12.7M86.4 82.6v12.7M124.5 80h13.9M158.7 87.6h10.2M158.7 95.3h10.2"/>
<path d="M162.6 90.2h6.3M162.6 92.7h6.3M191.8 87.6h10.1M191.8 95.3h10.1M195.6 90.2h6.3M195.6 92.7h6.3M224.8 87.6h10.1M224.8 95.3h10.1M228.6 90.2h6.3M228.6 92.7h6.3M257.8 87.6h10.2M257.8 95.3h10.2"/>
<path d="M261.6 90.2h6.4M261.6 92.7h6.4M16.5 110.5h11.4v12.7h5.1M25.4 110.5v1.3M25.4 119.4v1.3M33 105.4h12.7v10.2M105.4 118.1h29.2M114.3 118.1v3.8M121.9 118.1v3.8M151.1 113h8.9M151.1 115.6h8.9M154.9 110.5h5.1"/>
<path d="M172.7 113h8.9M172.7 115.6h8.9M176.5 110.5h5.1M205.7 108h16.5M248.9 116.8h11.4M257.8 111.8h2.5M260.3 114.3h-2.5v5.1M273 116.8h8.9M25.4 130.8v1.3M25.4 139.7v1.3M29.2 125.7h3.8M33 128.3h-5.1v12.7h-11.4"/>
<path d="M45.7 135.9v2.5h15.3M58.4 120.7h7.6M58.4 123.2h7.6M58.4 130.8v7.6M90.2 123.2h7.6M96.5 123.2v1.3M105.4 128.3v5.1M114.3 129.5v3.9M121.9 125.7v7.7h-25.4v-1.3M154.9 139.7h12.7M165.1 134.6h2.5M180.3 134.6h15.3v22.9"/>
<path d="M180.3 139.7h12.7M180.3 137.2h12.7M205.7 120.7h16.5M207 133.4h24.1M228.6 130.8h2.5M231.1 135.9v5.1h-13.9M248.9 138.4h11.4M257.8 133.4h2.5M260.3 135.9h-2.5v5.1M273 138.4h8.9M27.9 158.8h10.2M50.8 158.8h7.6"/>
<path d="M102.9 149.9v8.9M115.6 149.9v8.9M154.9 157.5h12.7M165.1 152.4h2.5M180.3 157.5h12.7M180.3 152.4h15.3M180.3 154.9h12.7M207 151.1h24.1M228.6 148.6h2.5M231.1 153.7v5.1h-13.9M27.9 168.9h10.2M27.9 163.8h10.2"/>
<path d="M30.5 171.5h7.6M38.1 161.3h-10.2v10.2M50.8 161.3h7.6M50.8 171.5h7.6M50.8 168.9h7.6M82.5 174h33.1M16.5 189.2h59.7M16.5 191.8h59.7M20.3 186.7h55.9M104.1 193h15.3M135.9 195.6h12.7M135.9 185.4h12.7"/>
<path d="M139.7 190.5h8.9M157.5 195.6h12.7M157.5 185.4h12.7M161.3 190.5h8.9"/>
</g>
<g fill="none" stroke="#000084" stroke-width=".18">
<path d="M98.5 56.5l1.2 1.3M98.5 46.4l1.2 1.2M98.5 48.9l1.2 1.2M98.5 59.1l1.2 1.2M99.7 56.5l-1.2 1.3M99.7 46.4l-1.2 1.2M99.7 48.9l-1.2 1.2M99.7 59.1l-1.2 1.2M123.9 56.5l1.2 1.3M125.1 56.5l-1.2 1.3M50.2 75.6l1.2 1.2M51.4 75.6l-1.2 1.2"/>
<path d="M123.9 71.8l1.2 1.2M125.1 71.8l-1.2 1.2M224.2 64.2l1.2 1.2M224.2 61.6l1.2 1.2M225.4 64.2l-1.2 1.2M225.4 61.6l-1.2 1.2M272.4 113.7l1.3 1.2M272.4 111.2l1.3 1.2M273.7 113.7l-1.3 1.2M273.7 111.2l-1.3 1.2M134 128.9l1.2 1.2M134 121.3l1.2 1.2"/>
<path d="M135.2 128.9l-1.2 1.2M135.2 121.3l-1.2 1.2M167 136.6l1.2 1.2M168.2 136.6l-1.2 1.2M272.4 132.7l1.3 1.3M272.4 135.3l1.3 1.2M273.7 132.7l-1.3 1.3M273.7 135.3l-1.3 1.2M37.5 155.6l1.2 1.2M38.7 155.6l-1.2 1.2M50.2 155.6l1.2 1.2M51.4 155.6l-1.2 1.2"/>
<path d="M167 154.3l1.2 1.2M168.2 154.3l-1.2 1.2M37.5 165.8l1.2 1.2M38.7 165.8l-1.2 1.2M50.2 163.2l1.2 1.2M50.2 165.8l1.2 1.2M51.4 163.2l-1.2 1.2M51.4 165.8l-1.2 1.2"/>
</g>
<g fill="none" stroke="#0000c2" stroke-width=".18" stroke-dasharray="1.7 .6">
<path d="M12.7 12.7h64.8v24.1h-64.8zM78.7 12.7h66.1v85.1h-66.1zM146 12.7h108v66h-108zM255.3 12.7h29.2v66h-29.2zM12.7 38.1h64.8v25.4h-64.8zM12.7 64.8h64.8v33h-64.8zM12.7 99.1h64.8v47h-64.8zM78.7 99.1h66.1v47h-66.1zM146 80h138.5v21.6h-138.5zM146 102.9h99.1v21.6h-99.1zM246.4 102.9h38.1v45.7h-38.1zM146 125.7h57.2v39.4h-57.2z"/>
<path d="M204.5 125.7h40.6v39.4h-40.6zM12.7 147.3h64.8v31.8h-64.8zM78.7 147.3h48.3v31.8h-48.3zM128.3 147.3h16.5v31.8h-16.5zM12.7 180.3h69.8v16.6h-69.8zM83.8 180.3h43.2v16.6h-43.2zM128.3 180.3h48.2v16.6h-48.2z"/>
</g>
<g fill="none" stroke="#0000c2" stroke-width=".18">
<path d="M161 14.1v.9M161.3 14.1l-.3 .3M262.2 14.6v.3M28.1 39.6l.2-.1 .3 .1v.8M28.1 39.5v.9M26.6 66.6l.6-.1v-.2l-.4-.1-.2 .2 .1 .6h.5M180.6 72.4l-.3 .9h.7M180.6 74.9l.4 .1v.2l-.6 .2M180.9 72.9v.8M181 75.7l-.4 .1M182.1 75l-.3-.1-.3 .3 .1 .5h.5M182.1 74.5v1.3"/>
<path d="M182.3 72.5l-.6 1.2M191.3 70.9h-.1M191.3 71.2l-.2 .2 .2 .3M33.9 91.4h.5M33.9 90.7h.5M34.4 90.7v1l-.3 .2h-.3M34.5 94.7h.5M34.7 94.3v1.1l.3 .2M35 92.8l-.3-.1-.1 .2v.2l.4 .1v.3h-.4M39.1 94.3h.8l-.5 .5 .4 .1 .1 .5-.3 .2h-.4M40 92.4v.4l-.7 .7h.8M48.5 94.7l.4 .1"/>
<path d="M48.7 92.7l.4 .1M48.9 95.5l-.4 .1M48.9 94.3v1.3M49.1 93.5h-.4M49.1 92.3v1.2M54.1 91.1h.8M153 81.9v.3M28.6 100.5v.8M29 100.5l-.4 .2M91.6 100.5h.5M91.8 100.1v1.1l.3 .1M153 104.8v.3"/>
<path d="M253.4 104.8v.3M153.8 127.2v.8M154.2 127.2l-.4 .2M212.4 127.2h.3M212.4 127.6h.3v.2l-.2 .2h-.2M24 143.3l.2 .3-.6 .1M24.2 144.1h-.2M35.4 143.4l.2-.1h.3l.1 .8M36.6 144.1l-.1 .2M48.3 142.8h.8M48.3 144l.2 .1M50.6 143.3v1.2"/>
<path d="M50.6 144.1h.4M51 143.3h-.4M154.1 172.3v.3l.4 .1 .1 .2-.2 .1h-.4M157.3 170.2h.4M157.7 170.2v1l-.3 .2M157.7 170.9l-.4 .1M158.4 174.3l-.3-.1-.2 .2v.2l.5 .1v.3h-.5M159.5 171.9v.4l-.8 .7h.8M163.4 173.8l-.4 .5 .3 .1 .1 .5-.3 .2h-.3M175.7 172.3l.1 .2-.6 .1M92.6 182.5l.1 .1h.4M93.1 181.8v1l-.2 .2h-.3"/>
<path d="M93.1 181.8h-.4l-.1 .1M145.8 181.8h.4l.1 .8"/>
</g>
<path d="M68.6 73.7v1.2M68.6 80v1.3M105.4 110.5v1.3M105.4 116.8v1.3" fill="none" stroke="#9c9b98" stroke-width=".18"/>
<path d="M67 73.9l3.2 7.2M70.2 73.9l-3.2 7.2M103.8 110.7l3.2 7.2M107 110.7l-3.2 7.2" fill="none" stroke="#e12e31" stroke-width=".46"/>
<path d="M123.4 56.7h.8M100.6 69.4h.7M123.4 69.4h.8M222.5 61.8h.7" fill="none" stroke="#a90000" stroke-width=".18"/>
<g fill="#009600" stroke="#009600" stroke-width=".18">
<circle cx="38.1" cy="191.8" r=".46"/>
<circle cx="44.4" cy="191.8" r=".46"/>
<circle cx="57.1" cy="189.2" r=".46"/>
<circle cx="57.1" cy="191.8" r=".46"/>
<circle cx="63.5" cy="186.7" r=".46"/>
<circle cx="57.1" cy="186.7" r=".46"/>
<circle cx="50.8" cy="191.8" r=".46"/>
<circle cx="69.8" cy="191.8" r=".46"/>
<circle cx="69.8" cy="186.7" r=".46"/>
<circle cx="63.5" cy="191.8" r=".46"/>
<circle cx="63.5" cy="189.2" r=".46"/>
<circle cx="69.8" cy="189.2" r=".46"/>
<circle cx="92.7" cy="174" r=".46"/>
<circle cx="102.9" cy="174" r=".46"/>
<circle cx="82.5" cy="174" r=".46"/>
<circle cx="109.2" cy="193" r=".46"/>
<circle cx="114.3" cy="193" r=".46"/>
<circle cx="104.1" cy="193" r=".46"/>
<circle cx="27.9" cy="163.8" r=".46"/>
<circle cx="27.9" cy="168.9" r=".46"/>
<circle cx="96.5" cy="133.4" r=".46"/>
<circle cx="105.4" cy="133.4" r=".46"/>
<circle cx="121.9" cy="118.1" r=".46"/>
<circle cx="114.3" cy="118.1" r=".46"/>
<circle cx="96.5" cy="123.2" r=".46"/>
<circle cx="105.4" cy="118.1" r=".46"/>
<circle cx="121.9" cy="129.5" r=".46"/>
<circle cx="114.3" cy="133.4" r=".46"/>
<circle cx="25.4" cy="141" r=".46"/>
<circle cx="25.4" cy="110.5" r=".46"/>
<circle cx="58.4" cy="138.4" r=".46"/>
<circle cx="33" cy="105.4" r=".46"/>
<circle cx="25.4" cy="191.8" r=".46"/>
<circle cx="25.4" cy="186.7" r=".46"/>
<circle cx="25.4" cy="189.2" r=".46"/>
<circle cx="38.1" cy="189.2" r=".46"/>
<circle cx="44.4" cy="189.2" r=".46"/>
<circle cx="38.1" cy="186.7" r=".46"/>
<circle cx="44.4" cy="186.7" r=".46"/>
<circle cx="31.7" cy="186.7" r=".46"/>
<circle cx="31.7" cy="189.2" r=".46"/>
<circle cx="31.7" cy="191.8" r=".46"/>
<circle cx="50.8" cy="186.7" r=".46"/>
<circle cx="50.8" cy="189.2" r=".46"/>
<circle cx="109.2" cy="25.4" r=".46"/>
<circle cx="118.1" cy="25.4" r=".46"/>
<circle cx="104.1" cy="25.4" r=".46"/>
<circle cx="66" cy="21.6" r=".46"/>
<circle cx="66" cy="24.1" r=".46"/>
<circle cx="47" cy="33" r=".46"/>
<circle cx="47" cy="19.1" r=".46"/>
<circle cx="26.7" cy="24.1" r=".46"/>
<circle cx="24.1" cy="33" r=".46"/>
<circle cx="24.1" cy="24.1" r=".46"/>
<circle cx="35.6" cy="21.6" r=".46"/>
<circle cx="31.7" cy="21.6" r=".46"/>
<circle cx="36.8" cy="19.1" r=".46"/>
<circle cx="35.6" cy="33" r=".46"/>
<circle cx="68.6" cy="73.7" r=".46"/>
<circle cx="35.6" cy="83.8" r=".46"/>
<circle cx="55.9" cy="48.3" r=".46"/>
<circle cx="33" cy="48.3" r=".46"/>
<circle cx="29.2" cy="48.3" r=".46"/>
<circle cx="95.2" cy="33" r=".46"/>
<circle cx="86.4" cy="33" r=".46"/>
<circle cx="86.4" cy="25.4" r=".46"/>
<circle cx="95.2" cy="25.4" r=".46"/>
<circle cx="29.2" cy="58.4" r=".46"/>
<circle cx="43.2" cy="58.4" r=".46"/>
<circle cx="33" cy="76.2" r=".46"/>
<circle cx="111.8" cy="87.6" r=".46"/>
<circle cx="86.4" cy="74.9" r=".46"/>
<circle cx="96.5" cy="87.6" r=".46"/>
<circle cx="205.7" cy="120.7" r=".46"/>
<circle cx="205.7" cy="108" r=".46"/>
<circle cx="257.8" cy="87.6" r=".46"/>
<circle cx="257.8" cy="95.3" r=".46"/>
<circle cx="158.7" cy="95.3" r=".46"/>
<circle cx="191.8" cy="95.3" r=".46"/>
<circle cx="224.8" cy="95.3" r=".46"/>
<circle cx="195.6" cy="152.4" r=".46"/>
<circle cx="227.3" cy="133.4" r=".46"/>
<circle cx="227.3" cy="151.1" r=".46"/>
<circle cx="227.3" cy="141" r=".46"/>
<circle cx="217.2" cy="158.8" r=".46"/>
<circle cx="217.2" cy="151.1" r=".46"/>
<circle cx="227.3" cy="158.8" r=".46"/>
<circle cx="217.2" cy="141" r=".46"/>
<circle cx="217.2" cy="133.4" r=".46"/>
<circle cx="175.3" cy="52.1" r=".46"/>
<circle cx="167.6" cy="49.5" r=".46"/>
<circle cx="174" cy="31.8" r=".46"/>
<circle cx="174" cy="34.3" r=".46"/>
<circle cx="174" cy="19.1" r=".46"/>
<circle cx="158.7" cy="87.6" r=".46"/>
<circle cx="149.9" cy="52.1" r=".46"/>
<circle cx="167.6" cy="64.8" r=".46"/>
<circle cx="175.3" cy="64.8" r=".46"/>
<circle cx="182.9" cy="54.6" r=".46"/>
<circle cx="149.9" cy="49.5" r=".46"/>
<circle cx="182.9" cy="64.8" r=".46"/>
<circle cx="189.2" cy="59.7" r=".46"/>
<circle cx="189.2" cy="62.2" r=".46"/>
<circle cx="191.8" cy="87.6" r=".46"/>
<circle cx="224.8" cy="87.6" r=".46"/>
</g>
<use href="#words"/>
</svg>
